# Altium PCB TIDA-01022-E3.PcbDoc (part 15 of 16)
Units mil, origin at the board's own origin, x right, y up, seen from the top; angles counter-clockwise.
Board outline 6929.13 x 11614.17 mil, 12 copper layers (L1_Top Layer, L2_GND, L3_GND, L4_Signal Layer 1, L5_GND, L6_PWR, L7_GND/PWR, L8_PWR, L9_GND/PWR, L10_Signal Layer 2, L11_GND, L12_Bottom Layer), stack 64.6 mil thick; 1733 components, 993 nets, 5987 pads, 3555 vias.

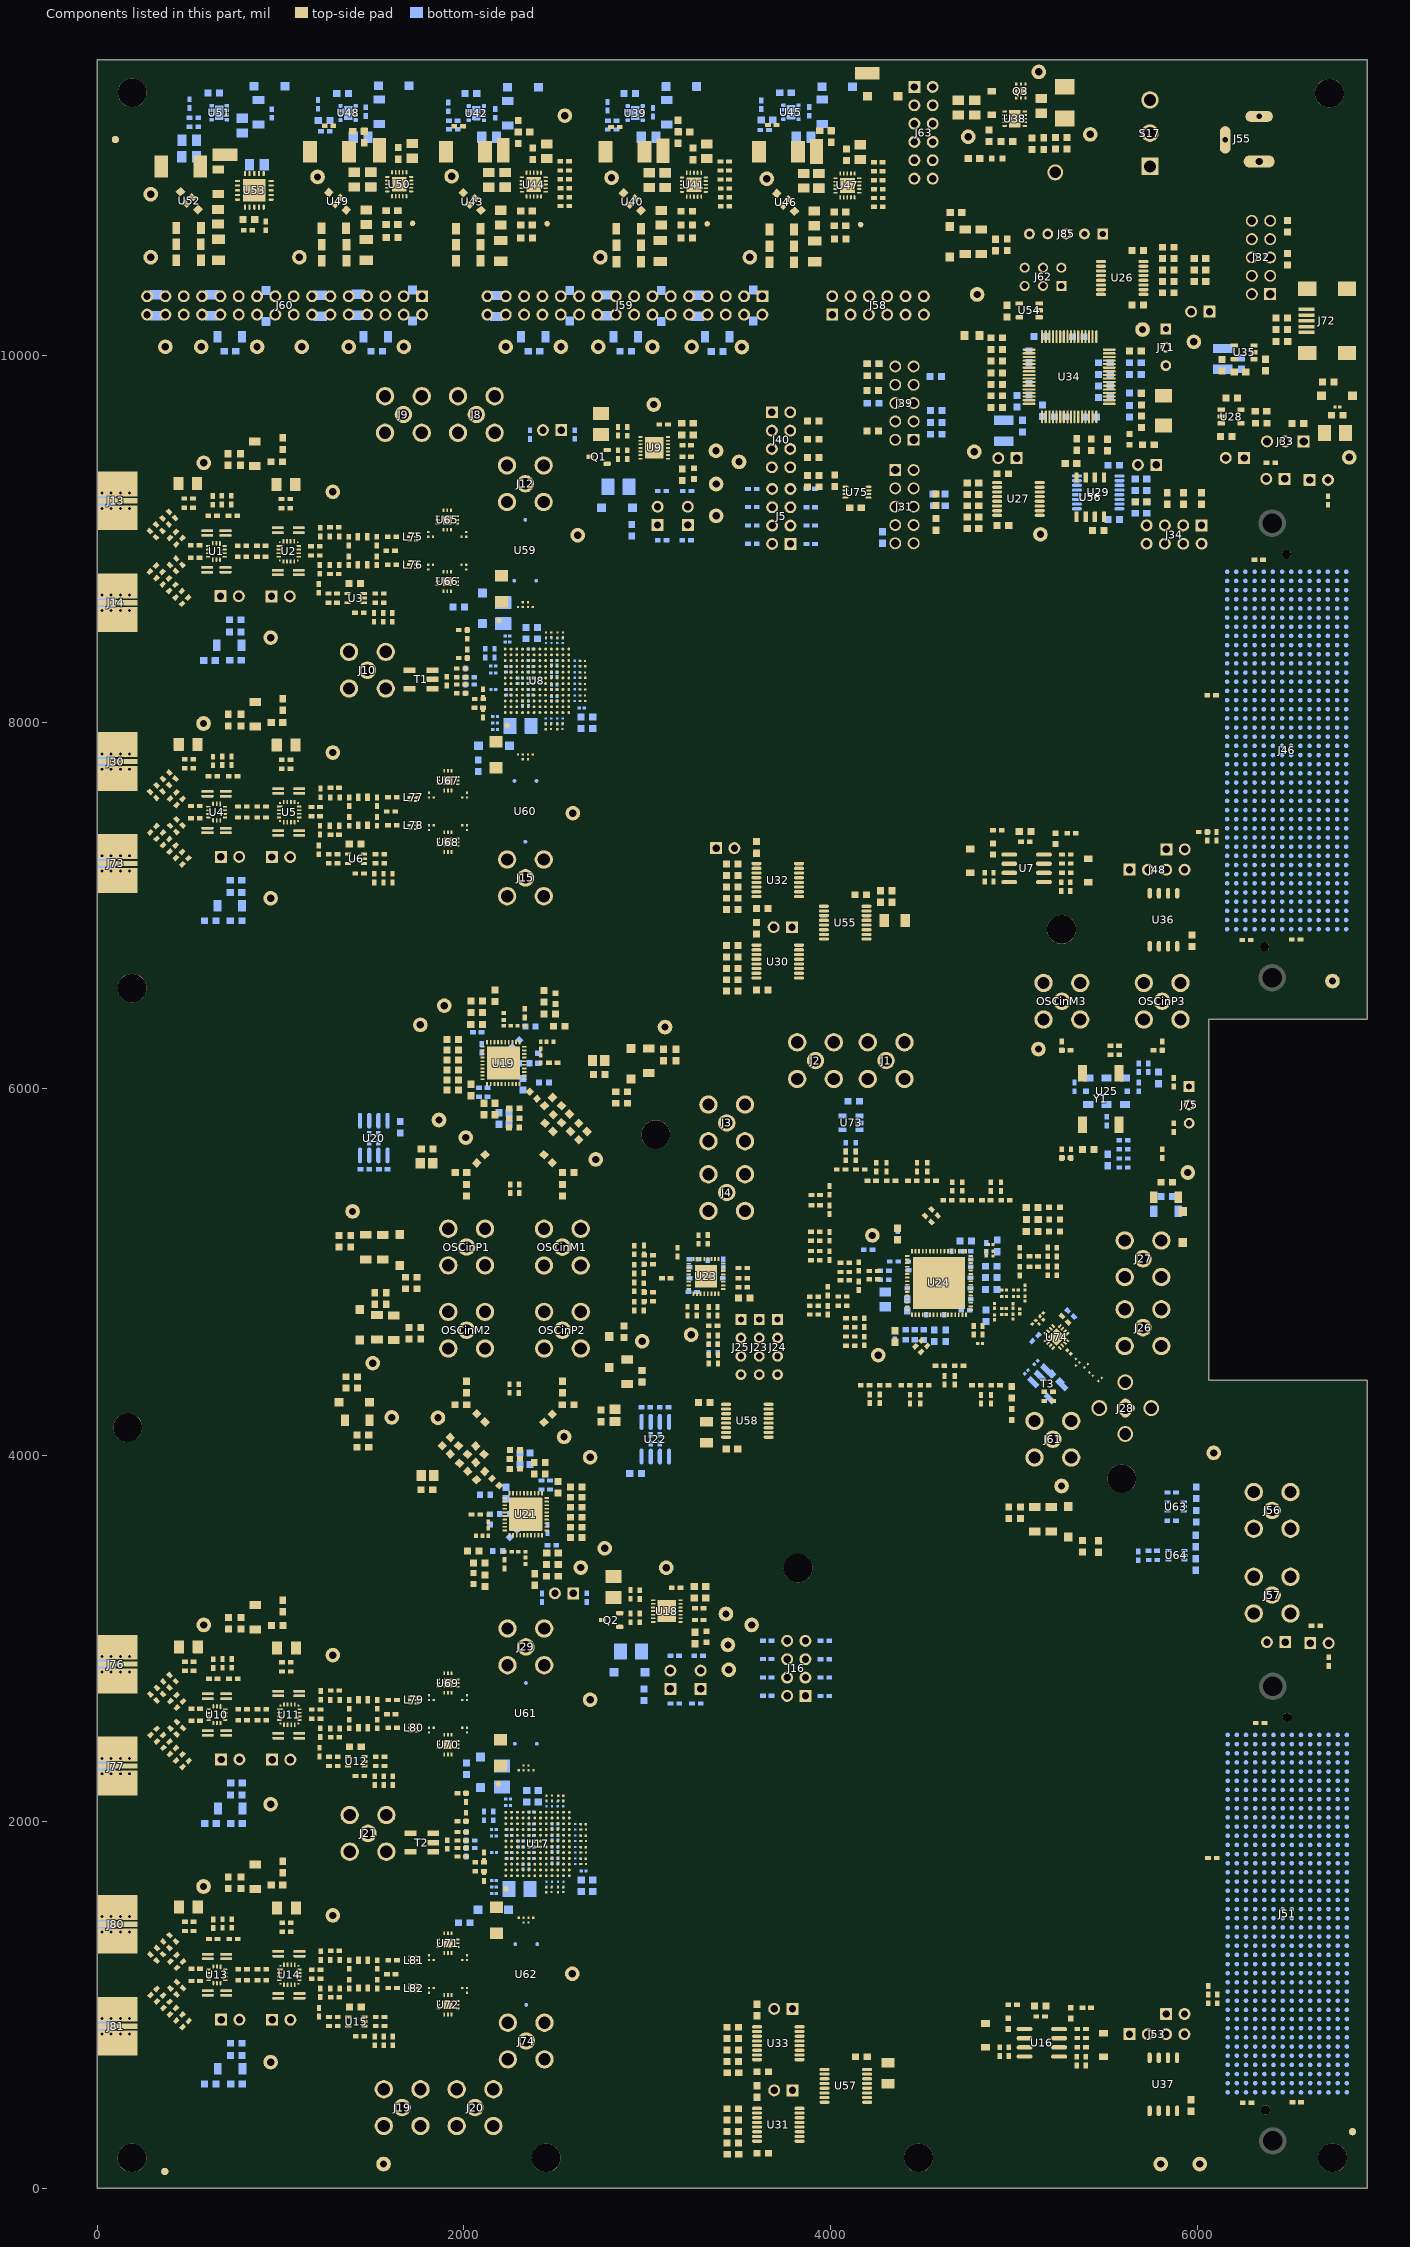
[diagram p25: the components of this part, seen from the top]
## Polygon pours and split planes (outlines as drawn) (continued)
VA1P9_ADC2 on L12_Bottom Layer "V" (solid, pour order 765): 2260,1490 2175,1490 2170,1495 2165,1500 2165,1595 2165,1690 2170,1695 2191.69,1695 2201.69,1685 2206.69,1680 2240,1680 2280,1680 2285,1675 2285,1510 2265,1490
VA1P9_ADC1 on L12_Bottom Layer "V" (solid, pour order 766): 2256.67,7836 2171.67,7836 2166.67,7841 2161.67,7846 2161.67,7941 2161.67,8029.27 2173.39,8041 2188.36,8041 2198.36,8031 2203.36,8026 2236.67,8026 2276.67,8026 2281.67,8021 2281.67,7856 2261.67,7836
VA1P1_ADC1 on L12_Bottom Layer "V" (solid, remove dead copper, pour order 767): 17 vertices, not listed, extent 2054.93,8436 2366.67,8576
NetC414_2 on L12_Bottom Layer "L1_Top Layer-No Net" (solid, pour order 782): 20 vertices, not listed, extent 5481,5542 5592,5770
DGND on L12_Bottom Layer "L1_Top Layer-No Net" (solid, pour order 783): 5606,5715 5606,5560 5615,5551 5667,5551 5673,5557 5673,5731 5666,5738 5618,5738 5606,5726
DGND on L12_Bottom Layer "L1_Top Layer-No Net" (solid, pour order 784): 5810,5448 5703,5448 5691,5436 5691,5298 5702,5287 5807,5287 5817,5297 5817,5441
V3P3_LMK61E2 on L12_Bottom Layer "L1_Top Layer-No Net" (solid, pour order 785): 5854,5285 5844,5295 5844,5452 5855,5463 6028,5463 6038,5453 6038,5300 6023,5285
DGND on L12_Bottom Layer "V" (solid, pour order 809): 2119,10255 2344,10255 2360,10239 2360,9998 2352,9990 2107,9990 2095,10002 2095,10221 2095,10245 2105,10255
DGND on L12_Bottom Layer "V" (solid, pour order 810): 2719,10255 2844,10255 2860,10239 2860,10001 2849,9990 2707,9990 2695,10002 2695,10221 2695,10245 2705,10255
DGND on L12_Bottom Layer "V" (solid, pour order 811): 3219,10255 3344,10255 3360,10239 3360,10001 3349,9990 3207,9990 3195,10002 3195,10221 3195,10245 3205,10255
V1P1V_IN on L12_Bottom Layer "V" (solid, pour order 831): 2405,10288 2392,10301 2392,10434 2410,10452 2655,10452 2664,10443 2664,10302 2650,10288
V1P9V_IN on L12_Bottom Layer "V" (solid, pour order 832): 2901,10288 2891,10298 2891,10414 2929,10452 3152,10452 3162,10442 3162,10301 3149,10288
GND on L12_Bottom Layer "V" (solid, pour order 833): 2696,10408 2696,10705 2720,10729 2721.64,10730.64 2817.51,10730.64 2850.67,10730.64 2861,10720.3 2861,10423 2861,10408 2861,10301 2851,10291 2712,10291 2696,10307
V3P3_IN on L12_Bottom Layer "V" (solid, pour order 834): 3393,10300 3393,10414 3398,10419 3878,10419 3893,10404 3893,10301 3881,10289 3404,10289 3393,10300
VA_N2P5 on L12_Bottom Layer "12" (solid, pour order 854): 743.2,8298.13 743.2,8343.13 743.2,8357.13 625.2,8357.13 616.2,8348.13 616.2,8311.13 616.2,8203.13 624.4,8194.93 732.15,8194.93 743.08,8205.85
NetC647_1 on L12_Bottom Layer "12" (solid, pour order 905): 21 vertices, not listed, extent 1199.9,11135.04 1424.41,11296.37
NetC495_1 on L12_Bottom Layer "12" (solid, pour order 908): 2991.2,11296.2 2968.15,11296.2 2966,11294.05 2966,11265.67 2960.65,11260.32 2907.31,11260.32 2901,11266.64 2901,11291.39 2816.52,11291.39 2816.52,11207.57 2816.52,11143.29 2824.94,11134.87 2980.99,11134.87 2991.2,11145.07 2991.2,11290.87
NetC538_1 on L12_Bottom Layer "12" (solid, pour order 911): 2124.2,11296.16 2101.16,11296.16 2099,11294 2099,11265.62 2093.65,11260.28 2040.31,11260.28 2034,11266.59 2034,11291.35 1949.53,11291.35 1949.53,11207.52 1949.52,11143.24 1957.94,11134.82 2113.99,11134.82 2124.2,11145.03 2124.2,11290.82
12VIN on L12_Bottom Layer "GNGN" (solid, pour order 938): 4092.72,11492.13 4098.72,11498.13 4211.98,11498.13 4215.97,11494.14 4215.97,11390.77 4210.2,11385 4095.79,11385 4092.58,11388.21
GND on L12_Bottom Layer "GNGN" (solid, remove dead copper, pour order 971): 31 vertices, not listed, extent 1168,11135.04 1819,11587
GND on L12_Bottom Layer "GNGN" (solid, remove dead copper, pour order 972): 1141.23,11376.2 1119.68,11376.2 1073.2,11376.2 1038,11341 1038,11144.09 1053.09,11129 1146,11129 1163,11146 1163,11357.05 1179.95,11373.99 1226.99,11373.99 1232.74,11379.74 1232.74,11404.16 1228.39,11408.51 1173.53,11408.51
GND on L12_Bottom Layer "GNGN" (solid, remove dead copper, pour order 973): 37 vertices, not listed, extent 1859.99,11137.39 2658.19,11587
GND on L12_Bottom Layer "GNGN" (solid, remove dead copper, pour order 974): 37 vertices, not listed, extent 2726.99,11137.44 3525.18,11587.05
GND on L12_Bottom Layer "GNGN" (solid, remove dead copper, pour order 975): 35 vertices, not listed, extent 3576,11141.57 4310.89,11591.18
VA_N2P5 on L12_Bottom Layer "12" (solid, remove dead copper, pour order 969): 748,6878 748,6923 748,6937 630,6937 621,6928 621,6891 621,6783 629.19,6774.81 736.94,6774.8 747.87,6785.72
VA_N2P5 on L12_Bottom Layer "12" (solid, pour order 967): 749.21,1953.05 749.21,1998.05 749.21,2012.05 631.21,2012.05 622.21,2003.05 622.21,1966.05 622.21,1858.05 630.41,1849.85 738.16,1849.85 749.09,1860.77
VA_N2P5 on L12_Bottom Layer "12" (solid, pour order 948): 747.59,532.43 747.59,577.43 747.59,591.43 629.59,591.43 620.59,582.43 620.59,545.43 620.59,437.43 628.79,429.23 736.54,429.23 747.47,440.15
VD1P1_ADC2 on L12_Bottom Layer "GNGN" (solid, remove dead copper, pour order 1066): 2881.44,2982 2759,2982 2759,2769.14 2735.72,2745.86 2631.06,2745.86 2612.87,2727.67 2612.87,2609.13 2622,2600 2856.5,2600 2872,2615.5 2872,2862.68 2893.32,2884 2893.32,2970.12
VD1P1_ADC1 on L12_Bottom Layer "GNGN" (solid, remove dead copper, pour order 1080): 2813.68,9335.41 2691.24,9335.41 2691.24,9122.55 2667.96,9099.27 2563.3,9099.27 2545.1,9081.08 2545.1,8962.55 2554.24,8953.41 2788.74,8953.41 2804.24,8968.91 2804.24,9216.09 2825.56,9237.41 2825.56,9323.53
V1P1V on L12_Bottom Layer "h" (solid, pour order 1082): 2858.26,9060.01 2852.94,9065.33 2852.94,9192.18 2867.18,9206.41 2969.31,9206.41 2986.27,9189.45 2986.27,9068.01 2978.26,9060
DGND on L12_Bottom Layer "12" (solid, remove dead copper, pour order 1086): 54 vertices, not listed, extent 1262,70 6899,10776
NetC695_2 on L6_PWR "L4_Signal Layer 1-No Net" (solid, remove dead copper, pour order 1060): 20,11038 20,10323.25 70.25,10273 1005,10273 1010,10278 1010,11320.56 955.56,11375 955.56,11577.43 945.99,11587 451.98,11587 379.83,11514.85 379.83,11397.83 355,11373
VA_N2P5_LMH5401_4 on L6_PWR "GNGN" (solid, remove dead copper, pour order 1008): 19 vertices, not listed, extent 358.46,565.46 1642.67,1686.3
VA_N2P5_LMH5401_3 on L6_PWR "GNGN" (solid, remove dead copper, pour order 1006): 19 vertices, not listed, extent 358.38,1984.8 1642.59,3105.64
VA_N2P5_LMH5401_2 on L6_PWR "GNGN" (solid, remove dead copper, pour order 1004): 19 vertices, not listed, extent 356.87,6909.03 1641.07,8029.87
VA_N2P5_LMH5401_1 on L6_PWR "GNGN" (solid, remove dead copper, pour order 981): 19 vertices, not listed, extent 355.07,8331.16 1639.28,9452
12VIN on L6_PWR "GNGN" (solid, pour order 970): 21 vertices, not listed, extent 977,11385 4268.73,11587
GND on L6_PWR "L4_Signal Layer 1-No Net" (solid, remove dead copper, pour order 966): 1351.38,11364 1060.42,11364 1038,11341.58 1038,10273 1801.91,10273 1813.91,10285 1819,10290.09 1819,10360.89 1819,11343.69 1798.69,11364
GND on L6_PWR "L4_Signal Layer 1-No Net" (solid, remove dead copper, pour order 965): 1860,11356.22 1860,10312 1881,10291 2658,10291 2658,11350.39 2644.39,11364 2352.82,11364 2338.34,11378.48 2338.34,11486.15 2328.48,11496 2042.15,11496 1914.23,11496 1860,11441.77 1860,11358.14
GND on L6_PWR "L4_Signal Layer 1-No Net" (solid, remove dead copper, pour order 964): 2696,11330 2696,10297 2702,10291 3164.19,10291 3165,10291.81 3165,10444 3525,10804 3525,11356.56 3517.56,11364 2708.43,11364 2696,11351.57
GND on L6_PWR "L4_Signal Layer 1-No Net" (solid, remove dead copper, pour order 963): 22 vertices, not listed, extent 3194,10291 4609,11587
V3P3_LMX2RF on L6_PWR "12" (solid, pour order 869): 1277.39,4363.39 1277.39,3765.61 1764,3279 2425,3279 2437,3291 2437,3526 2413,3550 2329,3550 2219,3660 1792,3660 1667,3785 1667,4337 1633,4371 1285,4371
V3P3_LMX2 on L6_PWR "12" (solid, pour order 868): 21 vertices, not listed, extent 1277.39,3310 3042,4642.68
V3P3_LMX1RF on L6_PWR "12" (solid, pour order 865): 2339,6260 2299,6220 1717,6220 1698,6239 1698,6391 1812,6505 1852,6545 2330,6545 3092,6545 3178,6545 3198.57,6524.43 3198.57,6400.77 3198.57,6296.57 3162,6260
V3P3 on L6_PWR "12" (solid, pour order 860): 17 vertices, not listed, extent 1277.39,4445.76 2837,5340
V3P3_LMX1 on L6_PWR "12" (solid, pour order 859): 1277.39,5185.61 1277.39,5962.43 1512.96,6198 2291.29,6198 2350.47,6257.18 2418.92,6257.18 2816.82,6257.18 2839.61,6234.39 2839.61,5481.61 2727,5369 1899,5369 1705.3,5175.3 1287.7,5175.3
V3P3_VDD on L6_PWR "12" (solid, pour order 858): 34 vertices, not listed, extent 2627,6376.24 6898,10801
V3P3_VDD on L6_PWR "12" (solid, pour order 857): 29 vertices, not listed, extent 2684,70 6082.44,4333
VA_N2P5 on L6_PWR "12" (solid, pour order 855): 44 vertices, not listed, extent 53,421.89 1003,10255
V3P3_LMK48XX on L6_PWR "V" (solid, pour order 815): 20 vertices, not listed, extent 3254,3743 6019,6344
V3P3_LMK61E2 on L6_PWR "V" (solid, pour order 814): 5702,5287 5526,5287 5400,5413 5074,5739 5074,6239 5074,6625 5126,6677 5919,6677 6018,6578 6018,5305.28 5999.72,5287 5703,5287
V3P3_LMK00304 on L6_PWR "V" (solid, pour order 813): 3741,4362 2912,4362 2882,4392 2860,4414 2860,4960 2860,5206 2898,5244 3372,5244 3678,5244 3753,5169 3760.74,5161.26 3760.74,4758 3760.74,4381.74
VREGIN on L6_PWR "V" (solid, pour order 812): 18 vertices, not listed, extent 5043.3,9556.44 5863.31,10075
V3P3 on L6_PWR "12" (solid, pour order 895): 4709,10776 4612,10776 4600,10764 4600,10216 4534,10150 3405,10150 3392,10137 3392,10000 3402,9990 4594,9990 4664,10060 4720,10116 4720,10765
GND on L6_PWR "GNGN" (solid, remove dead copper, pour order 978): 4586.81,11587 6805,11587 6865,11527 6865,10886 6808,10829 4604,10829 4599,10824 4576.5,10846.5 4576.5,11581
VD1P1_ADC2 on L6_PWR "GNGN" (solid, remove dead copper, pour order 1070): 2747,1546.22 2421.78,1546.22 2405.33,1562.67 2405.33,2469.31 2702.36,2766.34 2735.64,2799.62 2807.45,2799.62 2852.71,2799.62 2873.33,2779 2873.33,1578.26 2841,1545.93
V1P1V on L6_PWR "GNGN" (solid, remove dead copper, pour order 1072): 23 vertices, not listed, extent 1969.98,2259.91 3080.52,3008.69
VA1P9_ADC2 on L6_PWR "GNGN" (solid, remove dead copper, pour order 1074): 30 vertices, not listed, extent 1848.05,1034 4066.64,3026.61
VA1P9_ADC1 on L6_PWR "GNGN" (solid, remove dead copper, pour order 1076): 27 vertices, not listed, extent 1844.71,7380 3995.09,9308
VD1P1_ADC1 on L6_PWR "GNGN" (solid, remove dead copper, pour order 1078): 2743.67,7892.21 2418.45,7892.21 2402,7908.67 2402,8872.44 2675.18,9145.62 2804.12,9145.62 2825,9124.74 2825,7960.21 2756.76,7892.17
V1P1V on L6_PWR "GNGN" (solid, remove dead copper, pour order 1084): 20 vertices, not listed, extent 1966.65,8605.9 3000,9310.58
NetC695_2 on L8_PWR "L4_Signal Layer 1-No Net" (solid, remove dead copper, pour order 1062): 20,11038 20,10323.25 70.25,10273 1005,10273 1010,10278 1010,11320.56 955.56,11375 955.56,11577.43 945.99,11587 451.98,11587 379.45,11514.47 379.45,11397.45 355,11373
VA2P5_LMH5401_4 on L8_PWR "GNGN" (solid, remove dead copper, pour order 1002): 1343.68,836.04 403.73,836.04 371.19,868.58 371.19,1673.05 397.82,1699.68 409.89,1711.75 873.16,1711.75 916.46,1711.75 1036.21,1592 1300.36,1592 1335.64,1556.72 1358,1534.36 1358,850.36
VA2P5_LMH5401_3 on L8_PWR "GNGN" (solid, remove dead copper, pour order 1000): 1343.68,2256.32 403.73,2256.32 371.19,2288.86 371.19,3093.33 397.82,3119.95 409.89,3132.03 873.16,3132.03 916.46,3132.03 1036.21,3012.28 1300.36,3012.28 1335.64,2977 1358,2954.64 1358,2270.64
VA2P5_LMH5401_2 on L8_PWR "GNGN" (solid, remove dead copper, pour order 998): 1343.68,7180.56 403.73,7180.56 371.19,7213.09 371.19,8017.56 397.82,8044.19 409.89,8056.26 873.16,8056.26 916.46,8056.26 1036.21,7936.51 1300.36,7936.51 1335.64,7901.23 1358,7878.87 1358,7194.87
VA2P5_LMH5401_1 on L8_PWR "GNGN" (solid, remove dead copper, pour order 980): 1343.68,8602.68 403.73,8602.68 371.19,8635.22 371.19,9439.69 397.82,9466.32 409.89,9478.39 873.16,9478.39 922.33,9478.39 1030.72,9370 1289,9370 1335.64,9323.36 1358,9301 1358,8617
12VIN on L8_PWR "GNGN" (solid, pour order 961): 21 vertices, not listed, extent 977,11385 4268.73,11587
GND on L8_PWR "L4_Signal Layer 1-No Net" (solid, remove dead copper, pour order 960): 1351.38,11364 1060.42,11364 1038,11341.58 1038,10273 1801.91,10273 1813.91,10285 1819,10290.09 1819,10360.89 1819,11343.69 1798.69,11364
GND on L8_PWR "L4_Signal Layer 1-No Net" (solid, remove dead copper, pour order 959): 1860,11356.22 1860,10312 1881,10291 2658,10291 2658,11350.39 2644.39,11364 2352.82,11364 2338.34,11378.48 2338.34,11486.15 2328.48,11496 2042.15,11496 1914.23,11496 1860,11441.77 1860,11358.14
GND on L8_PWR "L4_Signal Layer 1-No Net" (solid, remove dead copper, pour order 958): 2696,11330 2696,10297 2702,10291 3164.19,10291 3165,10291.81 3165,10444 3525,10804 3525,11356.56 3517.56,11364 2708.43,11364 2696,11351.57
GND on L8_PWR "L4_Signal Layer 1-No Net" (solid, remove dead copper, pour order 957): 22 vertices, not listed, extent 3194,10291 4609,11587
V3P3_VDD on L8_PWR "12" (solid, pour order 863): 19 vertices, not listed, extent 2886,106 6083,7428
VDDL19 on L8_PWR "12" (solid, pour order 862): 4648,10658 4648,7526 4704,7470 4723,7451 5722,7451 6051,7451 6082,7482 6082,8935 6106,8959 6821,8959 6898,9036 6898,10751 6848,10801 4791,10801 4653,10663
V3P3 on L8_PWR "12" (solid, pour order 861): 22 vertices, not listed, extent 2374,3460 5598,10255
VA2P5 on L8_PWR "12" (solid, pour order 856): 45 vertices, not listed, extent 683,1617.22 1804,10255
VA1P1_ADC2 on L8_PWR "V" (solid, pour order 822): 2145.34,2235 2130.33,2220 2130.33,1743 2155.33,1718 2599,1718 2615.33,1734.33 2615.33,2209 2615.33,2220 2600.33,2235
VA1P1_ADC1 on L8_PWR "V" (solid, pour order 821): 2142.01,8581 2127,8566 2127,8089 2149,8067 2574,8067 2612,8105 2612,8555 2612,8566 2597,8581
VA1P9_ADC1 on L8_PWR "12" (solid, pour order 875): 2640,9187 2640,8061 2617,8038 2177,8038 2175,8036 2175,7864 2183,7856 2831,7856 2884,7909 2884,9185 2846,9223 2658,9223 2640,9205
VA1P9_ADC2 on L8_PWR "12" (solid, pour order 876): 2628.18,2698.18 2628.18,1722.18 2594,1688 2172,1688 2167,1683 2167,1511 2180.09,1497.91 2819.18,1497.91 2864,1542.73 2864,2702 2848,2718 2648,2718
GND on L8_PWR "GNGN" (solid, remove dead copper, pour order 979): 4586.81,11587 6856.56,11587 6874.56,11569 6874.56,10897.72 6805.84,10829 4604,10829 4599,10824 4576.5,10846.5 4576.5,11581
DGND on L2_GND "12" (solid, remove dead copper, pour order 879): 112 vertices, not listed, extent 1262,70 6899,10776
AGND on L2_GND "12" (solid, remove dead copper, pour order 878): 97 vertices, not listed, extent 17.27,71 2555.33,10255
GND on L2_GND "12" (solid, pour order 840): 1912.86,11496 1860,11443.14 1860,10312 1881,10291 1966,10291 4519,10291 4572,10344 4572,10797 4609,10834 4609,11087 4585,11111 4391.28,11111 4391.27,11437.55 4332.82,11496 4204.99,11496
GND on L2_GND "12" (solid, pour order 839): 22 vertices, not listed, extent 20,10273 6865,11587
GND on L11_GND "12" (solid, pour order 1056): 22 vertices, not listed, extent 20,10273 6865,11587
GND on L11_GND "12" (solid, pour order 949): 1912.86,11496 1860,11443.14 1860,10312 1881,10291 1966,10291 4519,10291 4572,10344 4572,10797 4609,10834 4609,11087 4585,11111 4391.28,11111 4391.27,11437.55 4332.82,11496 4204.99,11496
DGND on L11_GND "12" (solid, remove dead copper, pour order 853): 54 vertices, not listed, extent 1262,70 6899,10776
AGND on L11_GND "12" (solid, remove dead copper, pour order 852): 26 vertices, not listed, extent 2152,2042.38 2554.99,3108.38
AGND on L11_GND "12" (solid, remove dead copper, pour order 851): 24 vertices, not listed, extent 2121.91,650.23 2522,1716.23
AGND on L11_GND "12" (solid, remove dead copper, pour order 850): 25 vertices, not listed, extent 2140,6996.2 2517,8062.2
AGND on L11_GND "12" (solid, remove dead copper, pour order 849): 25 vertices, not listed, extent 2160,8388 2552,9454
AGND on L11_GND "12" (solid, remove dead copper, pour order 884): 47 vertices, not listed, extent 17.27,71 1804,10255
GND on L5_GND "12" (solid, pour order 1050): 22 vertices, not listed, extent 20,10273 6865,11587
GND on L5_GND "12" (solid, pour order 942): 1912.86,11496 1860,11443.14 1860,10312 1881,10291 1966,10291 4519,10291 4572,10344 4572,10797 4609,10834 4609,11087 4585,11111 4391.28,11111 4391.27,11437.55 4332.82,11496 4204.99,11496
DGND on L5_GND "12" (solid, remove dead copper, pour order 882): 101 vertices, not listed, extent 873,70 6899,10776
AGND on L5_GND "12" (solid, remove dead copper, pour order 883): 85 vertices, not listed, extent 17.27,71 2521.36,10255
GND on L3_GND "12" (solid, pour order 1048): 22 vertices, not listed, extent 20,10273 6865,11587
DGND on L3_GND "12" (solid, remove dead copper, pour order 881): 112 vertices, not listed, extent 1262,70 6899,10776
AGND on L3_GND "12" (solid, remove dead copper, pour order 880): 97 vertices, not listed, extent 17.27,71 2555.33,10255
GND on L3_GND "12" (solid, pour order 940): 1912.86,11496 1860,11443.14 1860,10312 1881,10291 1966,10291 4519,10291 4572,10344 4572,10797 4609,10834 4609,11087 4585,11111 4391.28,11111 4391.27,11437.55 4332.82,11496 4204.99,11496
GND on L7_GND/PWR "12" (solid, pour order 1052): 22 vertices, not listed, extent 20,10273 6865,11587
GND on L7_GND/PWR "12" (solid, pour order 944): 1912.86,11496 1860,11443.14 1860,10312 1881,10291 1966,10291 4519,10291 4572,10344 4572,10797 4609,10834 4609,11087 4585,11111 4391.28,11111 4391.27,11437.55 4332.82,11496 4204.99,11496
AGND on L7_GND/PWR "12" (solid, remove dead copper, pour order 886): 89 vertices, not listed, extent 17.27,71 2555.33,10255
V1P9V on L7_GND/PWR "12" (solid, remove dead copper, pour order 887): 100 vertices, not listed, extent 1262,103 6898,10776
GND on L9_GND/PWR "12" (solid, pour order 1054): 22 vertices, not listed, extent 20,10273 6865,11587
GND on L9_GND/PWR "12" (solid, pour order 946): 1912.86,11496 1860,11443.14 1860,10312 1881,10291 1966,10291 4519,10291 4572,10344 4572,10797 4609,10834 4609,11087 4585,11111 4391.28,11111 4391.27,11437.55 4332.82,11496 4204.99,11496
AGND on L9_GND/PWR "12" (solid, remove dead copper, pour order 888): 87 vertices, not listed, extent 17.27,71 2555.33,10255
V1P1V on L9_GND/PWR "12" (solid, remove dead copper, pour order 889): 100 vertices, not listed, extent 1262,103 6899,10776
V1P9V on L4_Signal Layer 1 "L1_Top Layer-No Net" (solid, pour order 864): 17 vertices, not listed, extent 2787,8961 6898,10801
VA2P5 on L4_Signal Layer 1 "L4_Signal Layer 1-No Net" (solid, remove dead copper, pour order 935): 50 vertices, not listed, extent 17,1587 1160,9490
GND on L4_Signal Layer 1 "L4_Signal Layer 1-No Net" (solid, remove dead copper, pour order 934): 22 vertices, not listed, extent 3194,10291 4609,11587
GND on L4_Signal Layer 1 "L4_Signal Layer 1-No Net" (solid, remove dead copper, pour order 933): 2696,11330 2696,10297 2702,10291 3164.19,10291 3165,10291.81 3165,10444 3525,10804 3525,11356.56 3517.56,11364 2708.43,11364 2696,11351.57
GND on L4_Signal Layer 1 "L4_Signal Layer 1-No Net" (solid, remove dead copper, pour order 932): 1860,11356.22 1860,10312 1881,10291 2658,10291 2658,11350.39 2644.39,11364 2352.82,11364 2338.34,11378.48 2338.34,11486.15 2328.48,11496 2042.15,11496 1914.23,11496 1860,11441.77 1860,11358.14
GND on L4_Signal Layer 1 "L4_Signal Layer 1-No Net" (solid, remove dead copper, pour order 931): 1351.38,11364 1060.42,11364 1038,11341.58 1038,10273 1801.91,10273 1813.91,10285 1819,10290.09 1819,10360.89 1819,11343.69 1798.69,11364
NetC695_2 on L4_Signal Layer 1 "L4_Signal Layer 1-No Net" (solid, remove dead copper, pour order 930): 20,11038 20,10323.25 70.25,10273 1005,10273 1010,10278 1010,11320.56 955.56,11375 955.56,11577.43 945.99,11587 451.98,11587 379.45,11514.47 379.45,11397.45 355,11373
12VIN on L4_Signal Layer 1 "GNGN" (solid, pour order 939): 21 vertices, not listed, extent 977,11385 4268.73,11587
GND on L4_Signal Layer 1 "GNGN" (solid, remove dead copper, pour order 976): 4586.81,11587 6856.56,11587 6865,11578.56 6865,10885.62 6808.38,10829 4604,10829 4599,10824 4576.5,10846.5 4576.5,11581
NetC695_2 on L10_Signal Layer 2 "L4_Signal Layer 1-No Net" (solid, remove dead copper, pour order 1064): 20,11038 20,10323.25 70.25,10273 1005,10273 1010,10278 1010,11320.56 955.56,11375 955.56,11577.43 945.99,11587 451.98,11587 379.45,11514.47 379.45,11397.45 355,11373
12VIN on L10_Signal Layer 2 "GNGN" (solid, pour order 955): 21 vertices, not listed, extent 977,11385 4268.73,11587
GND on L10_Signal Layer 2 "L4_Signal Layer 1-No Net" (solid, remove dead copper, pour order 954): 1351.38,11364 1060.42,11364 1038,11341.58 1038,10273 1801.91,10273 1813.91,10285 1819,10290.09 1819,10360.89 1819,11343.69 1798.69,11364
GND on L10_Signal Layer 2 "L4_Signal Layer 1-No Net" (solid, remove dead copper, pour order 953): 1860,11356.22 1860,10312 1881,10291 2658,10291 2658,11350.39 2644.39,11364 2352.82,11364 2338.34,11378.48 2338.34,11486.15 2328.48,11496 2042.15,11496 1914.23,11496 1860,11441.77 1860,11358.14
GND on L10_Signal Layer 2 "L4_Signal Layer 1-No Net" (solid, remove dead copper, pour order 952): 2696,11330 2696,10297 2702,10291 3164.19,10291 3165,10291.81 3165,10444 3525,10804 3525,11356.56 3517.56,11364 2708.43,11364 2696,11351.57
GND on L10_Signal Layer 2 "L4_Signal Layer 1-No Net" (solid, remove dead copper, pour order 951): 22 vertices, not listed, extent 3194,10291 4609,11587
VA_N2P5 on L10_Signal Layer 2 "L1_Top Layer-No Net" (solid, pour order 912): 742,10255 78,10255 17.27,10194.27 17.27,546.06 192.33,371 943.42,371 1650,1077.58 1650,10014.2 1409.19,10255
GND on L10_Signal Layer 2 "GNGN" (solid, remove dead copper, pour order 977): 4586.81,11587 6856.56,11587 6874.56,11569 6874.56,10897.72 6805.84,10829 4604,10829 4599,10824 4576.5,10846.5 4576.5,11581
GND on Bottom Solder "GNGN" (solid): 1769,10667 1451,10667 1385,10733 1062,10733 1037,10708 1037,10506.47 1058.47,10485 1540,10485 1760,10485 1810,10535 1810,10656 1799,10667
GND on Bottom Solder "GNGN" (solid): 1861,10698.26 1861,10500 1876,10485 1889,10485 2528,10485 2562,10519 2562,10703.26 2532.26,10733 1871,10733 1861,10723
GND on Bottom Solder "GNGN" (solid): 3293.71,10712.29 3273,10733 2704.24,10733 2696,10724.76 2696,10489.71 2700.71,10485 3184,10485 3293.71,10594.71
GND on Bottom Solder "GNGN" (solid): 4237,10733 3519.7,10733 3494.7,10708 3494.7,10506.47 3516.17,10485 3997.7,10485 4246,10485 4267.7,10506.7 4267.7,10702.3
GND on Bottom Solder "GNGN" (solid): 968.3,10733 251,10733 226,10708 226,10506.47 247.47,10485 729,10485 977.3,10485 996,10503.7 996,10705.3
GND on Bottom Solder "GNGN" (solid): 19 vertices, not listed, extent 1168,11285 1633,11587
GND on Bottom Solder "GNGN" (solid): 19 vertices, not listed, extent 1867.79,11284.78 2332.79,11586.78
GND on Bottom Solder "GNGN" (solid): 19 vertices, not listed, extent 2734.79,11284.83 3199.79,11586.83
GND on Bottom Solder "GNGN" (solid): 19 vertices, not listed, extent 3583.8,11288.96 4048.8,11590.96
NetC695_2 on Bottom Solder "GNGN" (solid): 19 vertices, not listed, extent 464.68,11286.82 774,11588.82

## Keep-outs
Keep-Out Layer:
  circle w10: c6412.44,259.01 r99.18
  circle w10: c6412.44,2739.01 r99.18
  circle w10: c6409.11,6605.01 r99.18
  circle w10: c6409.11,9085.01 r99.18
  text ".Layer_Name" at -2293.76,-2323.68 h60

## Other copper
L1_Top Layer:
  drawing of 110 lines, arcs and shapes, not listed
  text "L1_TOP LAYER" at -2294.53,-2305.19 h60
L4_Signal Layer 1:
  pour cut-out: 4334.26,10849.78 4334.26,11068.47 4160.44,11242.29 4051.79,11242.29 4051.79,11253 4164.67,11253 4344.35,11073.32 4344.35,10850
  text "'.Layer_Name'" at -2294.32,-2310.1 h60
L10_Signal Layer 2:
  pour cut-out: 4334.26,10849.78 4334.26,11068.47 4160.44,11242.29 4051.79,11242.29 4051.79,11253 4164.67,11253 4344.35,11073.32 4344.35,10850
  pour cut-out: 1650,2139.98 1308.61,2139.98 1244.63,2076 1244.63,1832.69 1650,1427.32
  pour cut-out: 1650,6715.07 1256.93,6322 1256.93,3753.07 1650,3360 1650,6715.07
  pour cut-out: 1650,9881.34 1626.66,9858 1492.94,9858 1448,9813.06 1448,9494.06 1486.06,9456 1639.07,9456 1650,9445.07
  pour cut-out: 1650,8510.93 1620.07,8481 1297.61,8481 1237.31,8420.7 1237.31,8184.98 1666,7756.29 1666,7755
  text "'.Layer_Name'" at -2296.32,-2321.1 h60
L2_GND:
  pour cut-out: 1188.92,1305.83 1188.92,1029.87 1202.49,1016.3 1625.08,1016.3 1660.39,1051.61 1660.39,1307.04 1638.13,1329.3 1212.39,1329.3
  pour cut-out: 1188.84,2725.17 1188.84,2449.21 1202.41,2435.64 1625,2435.64 1660.32,2470.95 1660.32,2726.38 1638.06,2748.64 1212.32,2748.64
  pour cut-out: 1187.32,7649.4 1187.32,7373.44 1200.89,7359.87 1623.49,7359.87 1658.8,7395.18 1658.8,7650.61 1636.54,7672.87 1210.8,7672.87
  pour cut-out: 1185.53,9071.53 1185.53,8795.57 1199.1,8782 1621.69,8782 1657,8817.31 1657,9072.74 1634.74,9095 1209,9095
  pour cut-out: 3201,10291 3194,10298 3194,10422 3560,10788 3560,11330 3525,11330 3525,10804 3165,10444 3165,10291.81 3165.81,10291
  pour cut-out: 2702,10291 2696,10297 2696,11330 2658,11330 2658,10291
  pour cut-out: 1038,10272.51 1038,11352.34 1010,11352.34 1010,10273
  pour cut-out: 4334.26,10849.78 4334.26,11068.47 4160.44,11242.29 4051.79,11242.29 4051.79,11253 4164.67,11253 4344.35,11073.32 4344.35,10850
  text "'.Layer_Name'" at -2293.32,-2319.1 h60
L5_GND:
  pour cut-out: 4334.26,10849.78 4334.26,11068.47 4160.44,11242.29 4051.79,11242.29 4051.79,11253 4164.67,11253 4344.35,11073.32 4344.35,10850
  pour cut-out: 1038,10272.51 1038,11352.34 1010,11352.34 1010,10273
  pour cut-out: 2702,10291 2696,10297 2696,11330 2658,11330 2658,10291
  pour cut-out: 3201,10291 3194,10298 3194,10422 3560,10788 3560,11330 3525,11330 3525,10804 3165,10444 3165,10291.81 3165.81,10291
  text "'.Layer_Name'" at -2296.32,-2322.1 h60
L6_PWR:
  pour cut-out: 4334.26,10849.78 4334.26,11068.47 4160.44,11242.29 4051.79,11242.29 4051.79,11253 4164.67,11253 4344.35,11073.32 4344.35,10850
  text "'.Layer_Name'" at -2296.32,-2322.1 h60
L7_GND/PWR:
  pour cut-out: 4334.26,10849.78 4334.26,11068.47 4160.44,11242.29 4051.79,11242.29 4051.79,11253 4164.67,11253 4344.35,11073.32 4344.35,10850
  pour cut-out: 1038,10272.51 1038,11352.34 1010,11352.34 1010,10273
  pour cut-out: 2702,10291 2696,10297 2696,11330 2658,11330 2658,10291
  pour cut-out: 3201,10291 3194,10298 3194,10422 3560,10788 3560,11330 3525,11330 3525,10804 3165,10444 3165,10291.81 3165.81,10291
  text "'.Layer_Name'" at -2295.32,-2318.1 h60
L3_GND:
  pour cut-out: 4334.26,10849.78 4334.26,11068.47 4160.44,11242.29 4051.79,11242.29 4051.79,11253 4164.67,11253 4344.35,11073.32 4344.35,10850
  pour cut-out: 1038,10272.51 1038,11352.34 1010,11352.34 1010,10273
  pour cut-out: 2702,10291 2696,10297 2696,11330 2658,11330 2658,10291
  pour cut-out: 3201,10291 3194,10298 3194,10422 3560,10788 3560,11330 3525,11330 3525,10804 3165,10444 3165,10291.81 3165.81,10291
  text "'.Layer_Name'" at -2294.32,-2314.1 h60
L8_PWR:
  pour cut-out: 4334.26,10849.78 4334.26,11068.47 4160.44,11242.29 4051.79,11242.29 4051.79,11253 4164.67,11253 4344.35,11073.32 4344.35,10850
  text "'.Layer_Name'" at -2296.32,-2319.1 h60
L9_GND/PWR:
  pour cut-out: 4334.26,10849.78 4334.26,11068.47 4160.44,11242.29 4051.79,11242.29 4051.79,11253 4164.67,11253 4344.35,11073.32 4344.35,10850
  pour cut-out: 1038,10272.51 1038,11352.34 1010,11352.34 1010,10273
  pour cut-out: 2702,10291 2696,10297 2696,11330 2658,11330 2658,10291
  pour cut-out: 3201,10291 3194,10298 3194,10422 3560,10788 3560,11330 3525,11330 3525,10804 3165,10444 3165,10291.81 3165.81,10291
  text "'.Layer_Name'" at -2295.32,-2320.1 h60
L11_GND:
  pour cut-out: 4334.26,10849.78 4334.26,11068.47 4160.44,11242.29 4051.79,11242.29 4051.79,11253 4164.67,11253 4344.35,11073.32 4344.35,10850
  pour cut-out: 1038,10272.51 1038,11352.34 1010,11352.34 1010,10273
  pour cut-out: 2702,10291 2696,10297 2696,11330 2658,11330 2658,10291
  pour cut-out: 3201,10291 3194,10298 3194,10422 3560,10788 3560,11330 3525,11330 3525,10804 3165,10444 3165,10291.81 3165.81,10291
  text "'.Layer_Name'" at -2295.32,-2320.1 h60
L12_Bottom Layer:
  pour cut-out: 2410.33,2361 2651.33,2602 6093.33,2602 6866.33,2602 6899.33,2569 6899.33,422 6855.33,378 6120.33,378 6081.33,417 6081.33,1045 2789.33,1045 2410.33,1424
  pour cut-out: 2407,8707 2648,8948 6090,8948 6863,8948 6896,8915 6896,6768 6852,6724 6117,6724 6078,6763 6078,7391 2786,7391 2407,7770
  pour cut-out: 5259.87,4804.87 5371.08,4694.08 5306.5,4629.5 5233,4703 5175,4645 5231,4589 5301,4659 5369.5,4590.5 5263.5,4484.5 5101.5,4646.5
  pour cut-out: 5319.16,4642.16 5319.16,4640.84 5303.5,4656.5 5303.5,4661.5 5326.41,4684.41 5341,4669.82 5341,4664
  region net NetC695_2: 688.18,11357.46 688.18,11410.4 692.78,11415 646.07,11415 642,11410.92 642,11343.1 643.09,11342 685.18,11342 686,11342.82
  region net GND: 1412.78,11300.28 1392.5,11300.28 1391.74,11299.51 1391.74,11282.96 1391.78,11282.92 1344.39,11282.92 1344.32,11283 1344.32,11453.25 1344.66,11453.59 1391.78,11453.59 1391.74,11453.55 1391.74,11322.4 1393.94,11320.2 1475.68,11320.2 1477,11318.89 1477,11291.95 1475,11289.95 1443.55,11289.95 1433.21,11300.29
  region net GND: 2112.57,11300.06 2092.29,11300.06 2091.53,11299.3 2091.53,11282.75 2091.57,11282.71 2044.18,11282.71 2044.11,11282.78 2044.11,11453.03 2044.45,11453.37 2091.57,11453.37 2091.53,11453.33 2091.53,11322.19 2093.73,11319.99 2175.48,11319.99 2176.79,11318.67 2176.79,11291.74 2174.79,11289.74 2143.34,11289.74 2133.01,11300.07
  region net GND: 2979.57,11300.11 2959.29,11300.11 2958.53,11299.35 2958.53,11282.79 2958.57,11282.75 2911.18,11282.75 2911.11,11282.83 2911.11,11453.08 2911.44,11453.42 2958.57,11453.42 2958.53,11453.38 2958.53,11322.23 2960.73,11320.03 3042.47,11320.03 3043.79,11318.72 3043.79,11291.78 3041.79,11289.78 3010.34,11289.78 3000,11300.12
  region net GND: 3828.58,11304.24 3808.3,11304.24 3807.53,11303.48 3807.53,11286.92 3807.57,11286.88 3760.19,11286.88 3760.11,11286.96 3760.11,11457.21 3760.45,11457.55 3807.57,11457.55 3807.53,11457.51 3807.53,11326.36 3809.73,11324.16 3891.48,11324.16 3892.8,11322.85 3892.8,11295.91 3890.8,11293.91 3859.35,11293.91 3849.01,11304.25
  pour cut-out: 2207.37,2010.23 ccw(c2214.2,2010.23) 2209.37,2005.4 ccw(c2216.62,2012.64) 2216.62,2002.4 2233.72,2002.4 ccw(c2233.72,2016.06) 2243.37,2006.4 ccw(c2236.13,2013.64) 2246.37,2013.64 2246.37,2027.74 ccw(c2232.72,2027.74) 2242.37,2037.4 ccw(c2237.54,2032.57) 2237.54,2039.4 2220.44,2039.4 ccw(c2220.44,2022.33) 2208.37,2034.4 ccw(c2210.79,2031.99) 2207.37,2031.99
  pour cut-out: 2207.37,1978.73 ccw(c2214.2,1978.73) 2209.37,1973.9 ccw(c2216.62,1981.15) 2216.62,1970.9 2233.72,1970.9 ccw(c2233.72,1984.56) 2243.37,1974.9 ccw(c2236.13,1982.15) 2246.37,1982.15 2246.37,1996.25 ccw(c2232.72,1996.25) 2242.37,2005.9 ccw(c2237.54,2001.08) 2237.54,2007.9 2220.44,2007.9 ccw(c2220.44,1990.83) 2208.37,2002.9 ccw(c2210.79,2000.49) 2207.37,2000.49
  pour cut-out: 2207.37,1884.24 ccw(c2214.2,1884.24) 2209.37,1879.42 ccw(c2216.62,1886.66) 2216.62,1876.42 2233.72,1876.42 ccw(c2233.72,1890.07) 2243.37,1880.42 ccw(c2236.13,1887.66) 2246.37,1887.66 2246.37,1901.76 ccw(c2232.72,1901.76) 2242.37,1911.42 ccw(c2237.54,1906.59) 2237.54,1913.42 2220.44,1913.42 ccw(c2220.44,1896.35) 2208.37,1908.42 ccw(c2210.79,1906) 2207.37,1906
  pour cut-out: 2207.37,1852.75 ccw(c2214.2,1852.75) 2209.37,1847.92 ccw(c2216.62,1855.16) 2216.62,1844.92 2233.72,1844.92 ccw(c2233.72,1858.58) 2243.37,1848.92 ccw(c2236.13,1856.16) 2246.37,1856.16 2246.37,1870.26 ccw(c2232.72,1870.26) 2242.37,1879.92 ccw(c2237.54,1875.09) 2237.54,1881.92 2220.44,1881.92 ccw(c2220.44,1864.85) 2208.37,1876.92 ccw(c2210.79,1874.51) 2207.37,1874.51
  pour cut-out: 2207.37,1758.26 ccw(c2214.2,1758.26) 2209.37,1753.43 ccw(c2216.62,1760.67) 2216.62,1750.43 2233.72,1750.43 ccw(c2233.72,1764.09) 2243.37,1754.43 ccw(c2236.13,1761.67) 2246.37,1761.67 2246.37,1775.77 ccw(c2232.72,1775.77) 2242.37,1785.43 ccw(c2237.54,1780.6) 2237.54,1787.43 2220.44,1787.43 ccw(c2220.44,1770.36) 2208.37,1782.43 ccw(c2210.79,1780.02) 2207.37,1780.02
  pour cut-out: 2207.37,1726.76 ccw(c2214.2,1726.76) 2209.37,1721.94 ccw(c2216.62,1729.18) 2216.62,1718.94 2233.72,1718.94 ccw(c2233.72,1732.59) 2243.37,1722.94 ccw(c2236.13,1730.18) 2246.37,1730.18 2246.37,1744.28 ccw(c2232.72,1744.28) 2242.37,1753.94 ccw(c2237.54,1749.11) 2237.54,1755.94 2220.44,1755.94 ccw(c2220.44,1738.86) 2208.37,1750.94 ccw(c2210.79,1748.52) 2207.37,1748.52
  pour cut-out: 2238.87,1758.26 ccw(c2245.7,1758.26) 2240.87,1753.43 ccw(c2248.11,1760.67) 2248.11,1750.43 2265.21,1750.43 ccw(c2265.21,1764.09) 2274.87,1754.43 ccw(c2267.63,1761.67) 2277.87,1761.67 2277.87,1775.77 ccw(c2264.21,1775.77) 2273.87,1785.43 ccw(c2269.04,1780.6) 2269.04,1787.43 2251.94,1787.43 ccw(c2251.94,1770.36) 2239.87,1782.43 ccw(c2242.28,1780.02) 2238.87,1780.02
  pour cut-out: 2270.37,1758.26 ccw(c2277.19,1758.26) 2272.37,1753.43 ccw(c2279.61,1760.67) 2279.61,1750.43 2296.71,1750.43 ccw(c2296.71,1764.09) 2306.37,1754.43 ccw(c2299.12,1761.67) 2309.37,1761.67 2309.37,1775.77 ccw(c2295.71,1775.77) 2305.37,1785.43 ccw(c2300.54,1780.6) 2300.54,1787.43 2283.44,1787.43 ccw(c2283.44,1770.36) 2271.37,1782.43 ccw(c2273.78,1780.02) 2270.37,1780.02
  pour cut-out: 2301.86,1695.27 ccw(c2308.69,1695.27) 2303.86,1690.44 ccw(c2311.1,1697.68) 2311.1,1687.44 2328.2,1687.44 ccw(c2328.2,1701.1) 2337.86,1691.44 ccw(c2330.62,1698.68) 2340.86,1698.68 2340.86,1712.78 ccw(c2327.2,1712.78) 2336.86,1722.44 ccw(c2332.03,1717.61) 2332.03,1724.44 2314.93,1724.44 ccw(c2314.93,1707.37) 2302.86,1719.44 ccw(c2305.28,1717.03) 2301.86,1717.03
  pour cut-out: 2333.36,1695.27 ccw(c2340.19,1695.27) 2335.36,1690.44 ccw(c2342.6,1697.68) 2342.6,1687.44 2359.7,1687.44 ccw(c2359.7,1701.1) 2369.36,1691.44 ccw(c2362.11,1698.68) 2372.36,1698.68 2372.36,1712.78 ccw(c2358.7,1712.78) 2368.36,1722.44 ccw(c2363.53,1717.61) 2363.53,1724.44 2346.43,1724.44 ccw(c2346.43,1707.37) 2334.36,1719.44 ccw(c2336.77,1717.03) 2333.36,1717.03
  pour cut-out: 2427.85,1695.27 ccw(c2434.67,1695.27) 2429.85,1690.44 ccw(c2437.09,1697.68) 2437.09,1687.44 2454.19,1687.44 ccw(c2454.19,1701.1) 2463.85,1691.44 ccw(c2456.6,1698.68) 2466.85,1698.68 2466.85,1712.78 ccw(c2453.19,1712.78) 2462.85,1722.44 ccw(c2458.02,1717.61) 2458.02,1724.44 2440.92,1724.44 ccw(c2440.92,1707.37) 2428.85,1719.44 ccw(c2431.26,1717.03) 2427.85,1717.03
  pour cut-out: 2427.85,1726.76 ccw(c2434.68,1726.76) 2429.85,1721.94 ccw(c2437.09,1729.18) 2437.09,1718.94 2454.19,1718.94 ccw(c2454.19,1732.59) 2463.85,1722.94 ccw(c2456.61,1730.18) 2466.85,1730.18 2466.85,1744.28 ccw(c2453.19,1744.28) 2462.85,1753.94 ccw(c2458.02,1749.11) 2458.02,1755.94 2440.92,1755.94 ccw(c2440.92,1738.86) 2428.85,1750.94 ccw(c2431.27,1748.52) 2427.85,1748.52
  pour cut-out: 2459.34,1726.76 ccw(c2466.17,1726.76) 2461.34,1721.94 ccw(c2468.58,1729.18) 2468.58,1718.94 2485.68,1718.94 ccw(c2485.68,1732.59) 2495.34,1722.94 ccw(c2488.1,1730.18) 2498.34,1730.18 2498.34,1744.28 ccw(c2484.68,1744.28) 2494.34,1753.94 ccw(c2489.51,1749.11) 2489.51,1755.94 2472.41,1755.94 ccw(c2472.41,1738.86) 2460.34,1750.94 ccw(c2462.76,1748.52) 2459.34,1748.52
  pour cut-out: 2459.34,1695.27 ccw(c2466.17,1695.27) 2461.34,1690.44 ccw(c2468.58,1697.68) 2468.58,1687.44 2485.68,1687.44 ccw(c2485.68,1701.1) 2495.34,1691.44 ccw(c2488.1,1698.68) 2498.34,1698.68 2498.34,1712.78 ccw(c2484.68,1712.78) 2494.34,1722.44 ccw(c2489.51,1717.61) 2489.51,1724.44 2472.41,1724.44 ccw(c2472.41,1707.37) 2460.34,1719.44 ccw(c2462.76,1717.03) 2459.34,1717.03
  pour cut-out: 2490.84,1726.76 ccw(c2497.67,1726.76) 2492.84,1721.94 ccw(c2500.08,1729.18) 2500.08,1718.94 2517.18,1718.94 ccw(c2517.18,1732.59) 2526.84,1722.94 ccw(c2519.6,1730.18) 2529.84,1730.18 2529.84,1744.28 ccw(c2516.18,1744.28) 2525.84,1753.94 ccw(c2521.01,1749.11) 2521.01,1755.94 2503.91,1755.94 ccw(c2503.91,1738.86) 2491.84,1750.94 ccw(c2494.25,1748.52) 2490.84,1748.52
  pour cut-out: 2490.84,1695.27 ccw(c2497.67,1695.27) 2492.84,1690.44 ccw(c2500.08,1697.68) 2500.08,1687.44 2517.18,1687.44 ccw(c2517.18,1701.1) 2526.84,1691.44 ccw(c2519.6,1698.68) 2529.84,1698.68 2529.84,1712.78 ccw(c2516.18,1712.78) 2525.84,1722.44 ccw(c2521.01,1717.61) 2521.01,1724.44 2503.91,1724.44 ccw(c2503.91,1707.37) 2491.84,1719.44 ccw(c2494.25,1717.03) 2490.84,1717.03
  pour cut-out: 2522.33,1726.76 ccw(c2529.16,1726.76) 2524.33,1721.94 ccw(c2531.58,1729.18) 2531.58,1718.94 2548.68,1718.94 ccw(c2548.68,1732.59) 2558.33,1722.94 ccw(c2551.09,1730.18) 2561.33,1730.18 2561.33,1744.28 ccw(c2547.68,1744.28) 2557.33,1753.94 ccw(c2552.51,1749.11) 2552.51,1755.94 2535.4,1755.94 ccw(c2535.4,1738.86) 2523.33,1750.94 ccw(c2525.75,1748.52) 2522.33,1748.52
  pour cut-out: 2522.33,1695.27 ccw(c2529.16,1695.27) 2524.33,1690.44 ccw(c2531.58,1697.68) 2531.58,1687.44 2548.68,1687.44 ccw(c2548.68,1701.1) 2558.33,1691.44 ccw(c2551.09,1698.68) 2561.33,1698.68 2561.33,1712.78 ccw(c2547.68,1712.78) 2557.33,1722.44 ccw(c2552.51,1717.61) 2552.51,1724.44 2535.4,1724.44 ccw(c2535.4,1707.37) 2523.33,1719.44 ccw(c2525.75,1717.03) 2522.33,1717.03
  pour cut-out: 2522.33,1758.26 ccw(c2529.16,1758.26) 2524.33,1753.43 ccw(c2531.58,1760.67) 2531.58,1750.43 2548.68,1750.43 ccw(c2548.68,1764.09) 2558.33,1754.43 ccw(c2551.09,1761.67) 2561.33,1761.67 2561.33,1775.77 ccw(c2547.68,1775.77) 2557.33,1785.43 ccw(c2552.51,1780.6) 2552.51,1787.43 2535.4,1787.43 ccw(c2535.4,1770.36) 2523.33,1782.43 ccw(c2525.75,1780.02) 2522.33,1780.02
  pour cut-out: 2553.83,1758.26 ccw(c2560.66,1758.26) 2555.83,1753.43 ccw(c2563.07,1760.67) 2563.07,1750.43 2580.17,1750.43 ccw(c2580.17,1764.09) 2589.83,1754.43 ccw(c2582.59,1761.67) 2592.83,1761.67 2592.83,1775.77 ccw(c2579.17,1775.77) 2588.83,1785.43 ccw(c2584,1780.6) 2584,1787.43 2566.9,1787.43 ccw(c2566.9,1770.36) 2554.83,1782.43 ccw(c2557.24,1780.02) 2553.83,1780.02
  pour cut-out: 2522.33,1978.73 ccw(c2529.16,1978.73) 2524.33,1973.9 ccw(c2531.58,1981.15) 2531.58,1970.9 2548.68,1970.9 ccw(c2548.68,1984.56) 2558.33,1974.9 ccw(c2551.09,1982.15) 2561.33,1982.15 2561.33,1996.25 ccw(c2547.68,1996.25) 2557.33,2005.9 ccw(c2552.51,2001.08) 2552.51,2007.9 2535.4,2007.9 ccw(c2535.4,1990.83) 2523.33,2002.9 ccw(c2525.75,2000.49) 2522.33,2000.49
  pour cut-out: 2553.83,1978.73 ccw(c2560.66,1978.73) 2555.83,1973.9 ccw(c2563.07,1981.15) 2563.07,1970.9 2580.17,1970.9 ccw(c2580.17,1984.56) 2589.83,1974.9 ccw(c2582.59,1982.15) 2592.83,1982.15 2592.83,1996.25 ccw(c2579.17,1996.25) 2588.83,2005.9 ccw(c2584,2001.08) 2584,2007.9 2566.9,2007.9 ccw(c2566.9,1990.83) 2554.83,2002.9 ccw(c2557.24,2000.49) 2553.83,2000.49
  pour cut-out: 2553.83,1947.24 ccw(c2560.66,1947.24) 2555.83,1942.41 ccw(c2563.07,1949.65) 2563.07,1939.41 2580.17,1939.41 ccw(c2580.17,1953.07) 2589.83,1943.41 ccw(c2582.59,1950.65) 2592.83,1950.65 2592.83,1964.75 ccw(c2579.17,1964.75) 2588.83,1974.41 ccw(c2584,1969.58) 2584,1976.41 2566.9,1976.41 ccw(c2566.9,1959.34) 2554.83,1971.41 ccw(c2557.24,1968.99) 2553.83,1968.99
  pour cut-out: 2524.08,1948.98 ccw(c2530.91,1948.98) 2526.08,1944.15 ccw(c2533.33,1951.4) 2533.33,1941.15 2550.43,1941.15 ccw(c2550.43,1954.81) 2560.08,1945.15 ccw(c2552.84,1952.4) 2563.08,1952.4 2563.08,1966.5 ccw(c2549.43,1966.5) 2559.08,1976.15 ccw(c2554.26,1971.33) 2554.26,1978.15 2537.15,1978.15 ccw(c2537.15,1961.08) 2525.08,1973.15 ccw(c2527.5,1970.74) 2524.08,1970.74
  pour cut-out: 2522.33,1915.74 ccw(c2529.16,1915.74) 2524.33,1910.91 ccw(c2531.58,1918.15) 2531.58,1907.91 2548.68,1907.91 ccw(c2548.68,1921.57) 2558.33,1911.91 ccw(c2551.09,1919.15) 2561.33,1919.15 2561.33,1933.26 ccw(c2547.68,1933.26) 2557.33,1942.91 ccw(c2552.51,1938.08) 2552.51,1944.91 2535.4,1944.91 ccw(c2535.4,1927.84) 2523.33,1939.91 ccw(c2525.75,1937.5) 2522.33,1937.5
  pour cut-out: 2553.83,1915.74 ccw(c2560.66,1915.74) 2555.83,1910.91 ccw(c2563.07,1918.15) 2563.07,1907.91 2580.17,1907.91 ccw(c2580.17,1921.57) 2589.83,1911.91 ccw(c2582.59,1919.15) 2592.83,1919.15 2592.83,1933.26 ccw(c2579.17,1933.26) 2588.83,1942.91 ccw(c2584,1938.08) 2584,1944.91 2566.9,1944.91 ccw(c2566.9,1927.84) 2554.83,1939.91 ccw(c2557.24,1937.5) 2553.83,1937.5
  pour cut-out: 2522.33,1884.24 ccw(c2529.16,1884.24) 2524.33,1879.41 ccw(c2531.58,1886.65) 2531.58,1876.41 2548.68,1876.41 ccw(c2548.68,1890.07) 2558.33,1880.41 ccw(c2551.09,1887.65) 2561.33,1887.65 2561.33,1901.76 ccw(c2547.68,1901.76) 2557.33,1911.41 ccw(c2552.51,1906.58) 2552.51,1913.41 2535.4,1913.41 ccw(c2535.4,1896.34) 2523.33,1908.41 ccw(c2525.75,1906) 2522.33,1906
  pour cut-out: 2553.83,1884.24 ccw(c2560.66,1884.24) 2555.83,1879.42 ccw(c2563.07,1886.66) 2563.07,1876.42 2580.17,1876.42 ccw(c2580.17,1890.07) 2589.83,1880.42 ccw(c2582.59,1887.66) 2592.83,1887.66 2592.83,1901.76 ccw(c2579.17,1901.76) 2588.83,1911.42 ccw(c2584,1906.59) 2584,1913.42 2566.9,1913.42 ccw(c2566.9,1896.34) 2554.83,1908.42 ccw(c2557.24,1906) 2553.83,1906
  pour cut-out: 2522.33,1852.75 ccw(c2529.16,1852.75) 2524.33,1847.92 ccw(c2531.58,1855.16) 2531.58,1844.92 2548.68,1844.92 ccw(c2548.68,1858.58) 2558.33,1848.92 ccw(c2551.09,1856.16) 2561.33,1856.16 2561.33,1870.26 ccw(c2547.68,1870.26) 2557.33,1879.92 ccw(c2552.51,1875.09) 2552.51,1881.92 2535.4,1881.92 ccw(c2535.4,1864.85) 2523.33,1876.92 ccw(c2525.75,1874.51) 2522.33,1874.51
  pour cut-out: 2555.99,1850.59 ccw(c2562.82,1850.59) 2557.99,1845.76 ccw(c2565.23,1853.01) 2565.23,1842.76 2582.33,1842.76 ccw(c2582.33,1856.42) 2591.99,1846.76 ccw(c2584.74,1854.01) 2594.99,1854.01 2594.99,1868.11 ccw(c2581.33,1868.11) 2590.99,1877.76 ccw(c2586.16,1872.93) 2586.16,1879.76 2569.06,1879.76 ccw(c2569.06,1862.69) 2556.99,1874.76 ccw(c2559.4,1872.35) 2555.99,1872.35
  pour cut-out: 2524.08,1823 ccw(c2530.91,1823) 2526.08,1818.17 ccw(c2533.33,1825.41) 2533.33,1815.17 2550.43,1815.17 ccw(c2550.43,1828.83) 2560.08,1819.17 ccw(c2552.84,1826.41) 2563.08,1826.41 2563.08,1840.51 ccw(c2549.43,1840.51) 2559.08,1850.17 ccw(c2554.26,1845.34) 2554.26,1852.17 2537.15,1852.17 ccw(c2537.15,1835.1) 2525.08,1847.17 ccw(c2527.5,1844.76) 2524.08,1844.76
  pour cut-out: 2553.83,1821.25 ccw(c2560.66,1821.25) 2555.83,1816.42 ccw(c2563.07,1823.67) 2563.07,1813.42 2580.17,1813.42 ccw(c2580.17,1827.08) 2589.83,1817.42 ccw(c2582.59,1824.67) 2592.83,1824.67 2592.83,1838.77 ccw(c2579.17,1838.77) 2588.83,1848.42 ccw(c2584,1843.6) 2584,1850.42 2566.9,1850.42 ccw(c2566.9,1833.35) 2554.83,1845.42 ccw(c2557.24,1843.01) 2553.83,1843.01
  pour cut-out: 2524.08,1788.01 ccw(c2530.91,1788.01) 2526.08,1783.18 ccw(c2533.33,1790.42) 2533.33,1780.18 2550.43,1780.18 ccw(c2550.43,1793.84) 2560.08,1784.18 ccw(c2552.84,1791.42) 2563.08,1791.42 2563.08,1805.52 ccw(c2549.43,1805.52) 2559.08,1815.18 ccw(c2554.26,1810.35) 2554.26,1817.18 2537.15,1817.18 ccw(c2537.15,1800.11) 2525.08,1812.18 ccw(c2527.5,1809.76) 2524.08,1809.76
  pour cut-out: 2553.83,1789.76 ccw(c2560.66,1789.76) 2555.83,1784.93 ccw(c2563.07,1792.17) 2563.07,1781.93 2580.17,1781.93 ccw(c2580.17,1795.59) 2589.83,1785.93 ccw(c2582.59,1793.17) 2592.83,1793.17 2592.83,1807.27 ccw(c2579.17,1807.27) 2588.83,1816.93 ccw(c2584,1812.1) 2584,1818.93 2566.9,1818.93 ccw(c2566.9,1801.86) 2554.83,1813.93 ccw(c2557.24,1811.51) 2553.83,1811.51
  pour cut-out: 2427.85,2041.72 ccw(c2434.67,2041.72) 2429.85,2036.9 ccw(c2437.09,2044.14) 2437.09,2033.9 2454.19,2033.9 ccw(c2454.19,2047.55) 2463.85,2037.9 ccw(c2456.6,2045.14) 2466.85,2045.14 2466.85,2059.24 ccw(c2453.19,2059.24) 2462.85,2068.9 ccw(c2458.02,2064.07) 2458.02,2070.9 2440.92,2070.9 ccw(c2440.92,2053.83) 2428.85,2065.9 ccw(c2431.26,2063.48) 2427.85,2063.48
  pour cut-out: 2429.11,2011.49 ccw(c2435.93,2011.49) 2431.11,2006.66 ccw(c2438.35,2013.9) 2438.35,2003.66 2455.45,2003.66 ccw(c2455.45,2017.32) 2465.11,2007.66 ccw(c2457.86,2014.9) 2468.11,2014.9 2468.11,2029 ccw(c2454.45,2029) 2464.11,2038.66 ccw(c2459.28,2033.83) 2459.28,2040.66 2442.18,2040.66 ccw(c2442.18,2023.59) 2430.11,2035.66 ccw(c2432.52,2033.25) 2429.11,2033.25
  pour cut-out: 2459.34,2041.72 ccw(c2466.17,2041.72) 2461.34,2036.9 ccw(c2468.58,2044.14) 2468.58,2033.9 2485.68,2033.9 ccw(c2485.68,2047.55) 2495.34,2037.9 ccw(c2488.1,2045.14) 2498.34,2045.14 2498.34,2059.24 ccw(c2484.68,2059.24) 2494.34,2068.9 ccw(c2489.51,2064.07) 2489.51,2070.9 2472.41,2070.9 ccw(c2472.41,2053.83) 2460.34,2065.9 ccw(c2462.76,2063.48) 2459.34,2063.48
  pour cut-out: 2459.34,2010.23 ccw(c2466.17,2010.23) 2461.34,2005.4 ccw(c2468.58,2012.64) 2468.58,2002.4 2485.68,2002.4 ccw(c2485.68,2016.06) 2495.34,2006.4 ccw(c2488.1,2013.64) 2498.34,2013.64 2498.34,2027.74 ccw(c2484.68,2027.74) 2494.34,2037.4 ccw(c2489.51,2032.57) 2489.51,2039.4 2472.41,2039.4 ccw(c2472.41,2022.33) 2460.34,2034.4 ccw(c2462.76,2031.99) 2459.34,2031.99
  pour cut-out: 2490.84,2041.72 ccw(c2497.67,2041.72) 2492.84,2036.9 ccw(c2500.08,2044.14) 2500.08,2033.9 2517.18,2033.9 ccw(c2517.18,2047.55) 2526.84,2037.9 ccw(c2519.6,2045.14) 2529.84,2045.14 2529.84,2059.24 ccw(c2516.18,2059.24) 2525.84,2068.9 ccw(c2521.01,2064.07) 2521.01,2070.9 2503.91,2070.9 ccw(c2503.91,2053.83) 2491.84,2065.9 ccw(c2494.25,2063.48) 2490.84,2063.48
  pour cut-out: 2490.84,2010.23 ccw(c2497.67,2010.23) 2492.84,2005.4 ccw(c2500.08,2012.64) 2500.08,2002.4 2517.18,2002.4 ccw(c2517.18,2016.06) 2526.84,2006.4 ccw(c2519.6,2013.64) 2529.84,2013.64 2529.84,2027.74 ccw(c2516.18,2027.74) 2525.84,2037.4 ccw(c2521.01,2032.57) 2521.01,2039.4 2503.91,2039.4 ccw(c2503.91,2022.33) 2491.84,2034.4 ccw(c2494.25,2031.99) 2490.84,2031.99
  pour cut-out: 2522.33,2010.23 ccw(c2529.16,2010.23) 2524.33,2005.4 ccw(c2531.58,2012.64) 2531.58,2002.4 2548.68,2002.4 ccw(c2548.68,2016.06) 2558.33,2006.4 ccw(c2551.09,2013.64) 2561.33,2013.64 2561.33,2027.74 ccw(c2547.68,2027.74) 2557.33,2037.4 ccw(c2552.51,2032.57) 2552.51,2039.4 2535.4,2039.4 ccw(c2535.4,2022.33) 2523.33,2034.4 ccw(c2525.75,2031.99) 2522.33,2031.99
  pour cut-out: 2522.33,2041.72 ccw(c2529.16,2041.72) 2524.33,2036.9 ccw(c2531.58,2044.14) 2531.58,2033.9 2548.68,2033.9 ccw(c2548.68,2047.55) 2558.33,2037.9 ccw(c2551.09,2045.14) 2561.33,2045.14 2561.33,2059.24 ccw(c2547.68,2059.24) 2557.33,2068.9 ccw(c2552.51,2064.07) 2552.51,2070.9 2535.4,2070.9 ccw(c2535.4,2053.83) 2523.33,2065.9 ccw(c2525.75,2063.48) 2522.33,2063.48
  pour cut-out: 2333.36,2041.72 ccw(c2340.19,2041.72) 2335.36,2036.9 ccw(c2342.6,2044.14) 2342.6,2033.9 2359.7,2033.9 ccw(c2359.7,2047.55) 2369.36,2037.9 ccw(c2362.11,2045.14) 2372.36,2045.14 2372.36,2059.24 ccw(c2358.7,2059.24) 2368.36,2068.9 ccw(c2363.53,2064.07) 2363.53,2070.9 2346.43,2070.9 ccw(c2346.43,2053.83) 2334.36,2065.9 ccw(c2336.77,2063.48) 2333.36,2063.48
  pour cut-out: 2301.86,2041.72 ccw(c2308.69,2041.72) 2303.86,2036.9 ccw(c2311.1,2044.14) 2311.1,2033.9 2328.2,2033.9 ccw(c2328.2,2047.55) 2337.86,2037.9 ccw(c2330.62,2045.14) 2340.86,2045.14 2340.86,2059.24 ccw(c2327.2,2059.24) 2336.86,2068.9 ccw(c2332.03,2064.07) 2332.03,2070.9 2314.93,2070.9 ccw(c2314.93,2053.83) 2302.86,2065.9 ccw(c2305.28,2063.48) 2301.86,2063.48
  text "'.Layer_Name'" at -2296.32,-2314.1 h60
Multi-Layer:
  drawing of 162 lines, arcs and shapes, not listed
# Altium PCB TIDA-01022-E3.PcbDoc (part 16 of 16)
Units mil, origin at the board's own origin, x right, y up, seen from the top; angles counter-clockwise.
Board outline 6929.13 x 11614.17 mil, 12 copper layers (L1_Top Layer, L2_GND, L3_GND, L4_Signal Layer 1, L5_GND, L6_PWR, L7_GND/PWR, L8_PWR, L9_GND/PWR, L10_Signal Layer 2, L11_GND, L12_Bottom Layer), stack 64.6 mil thick; 1733 components, 993 nets, 5987 pads, 3555 vias.

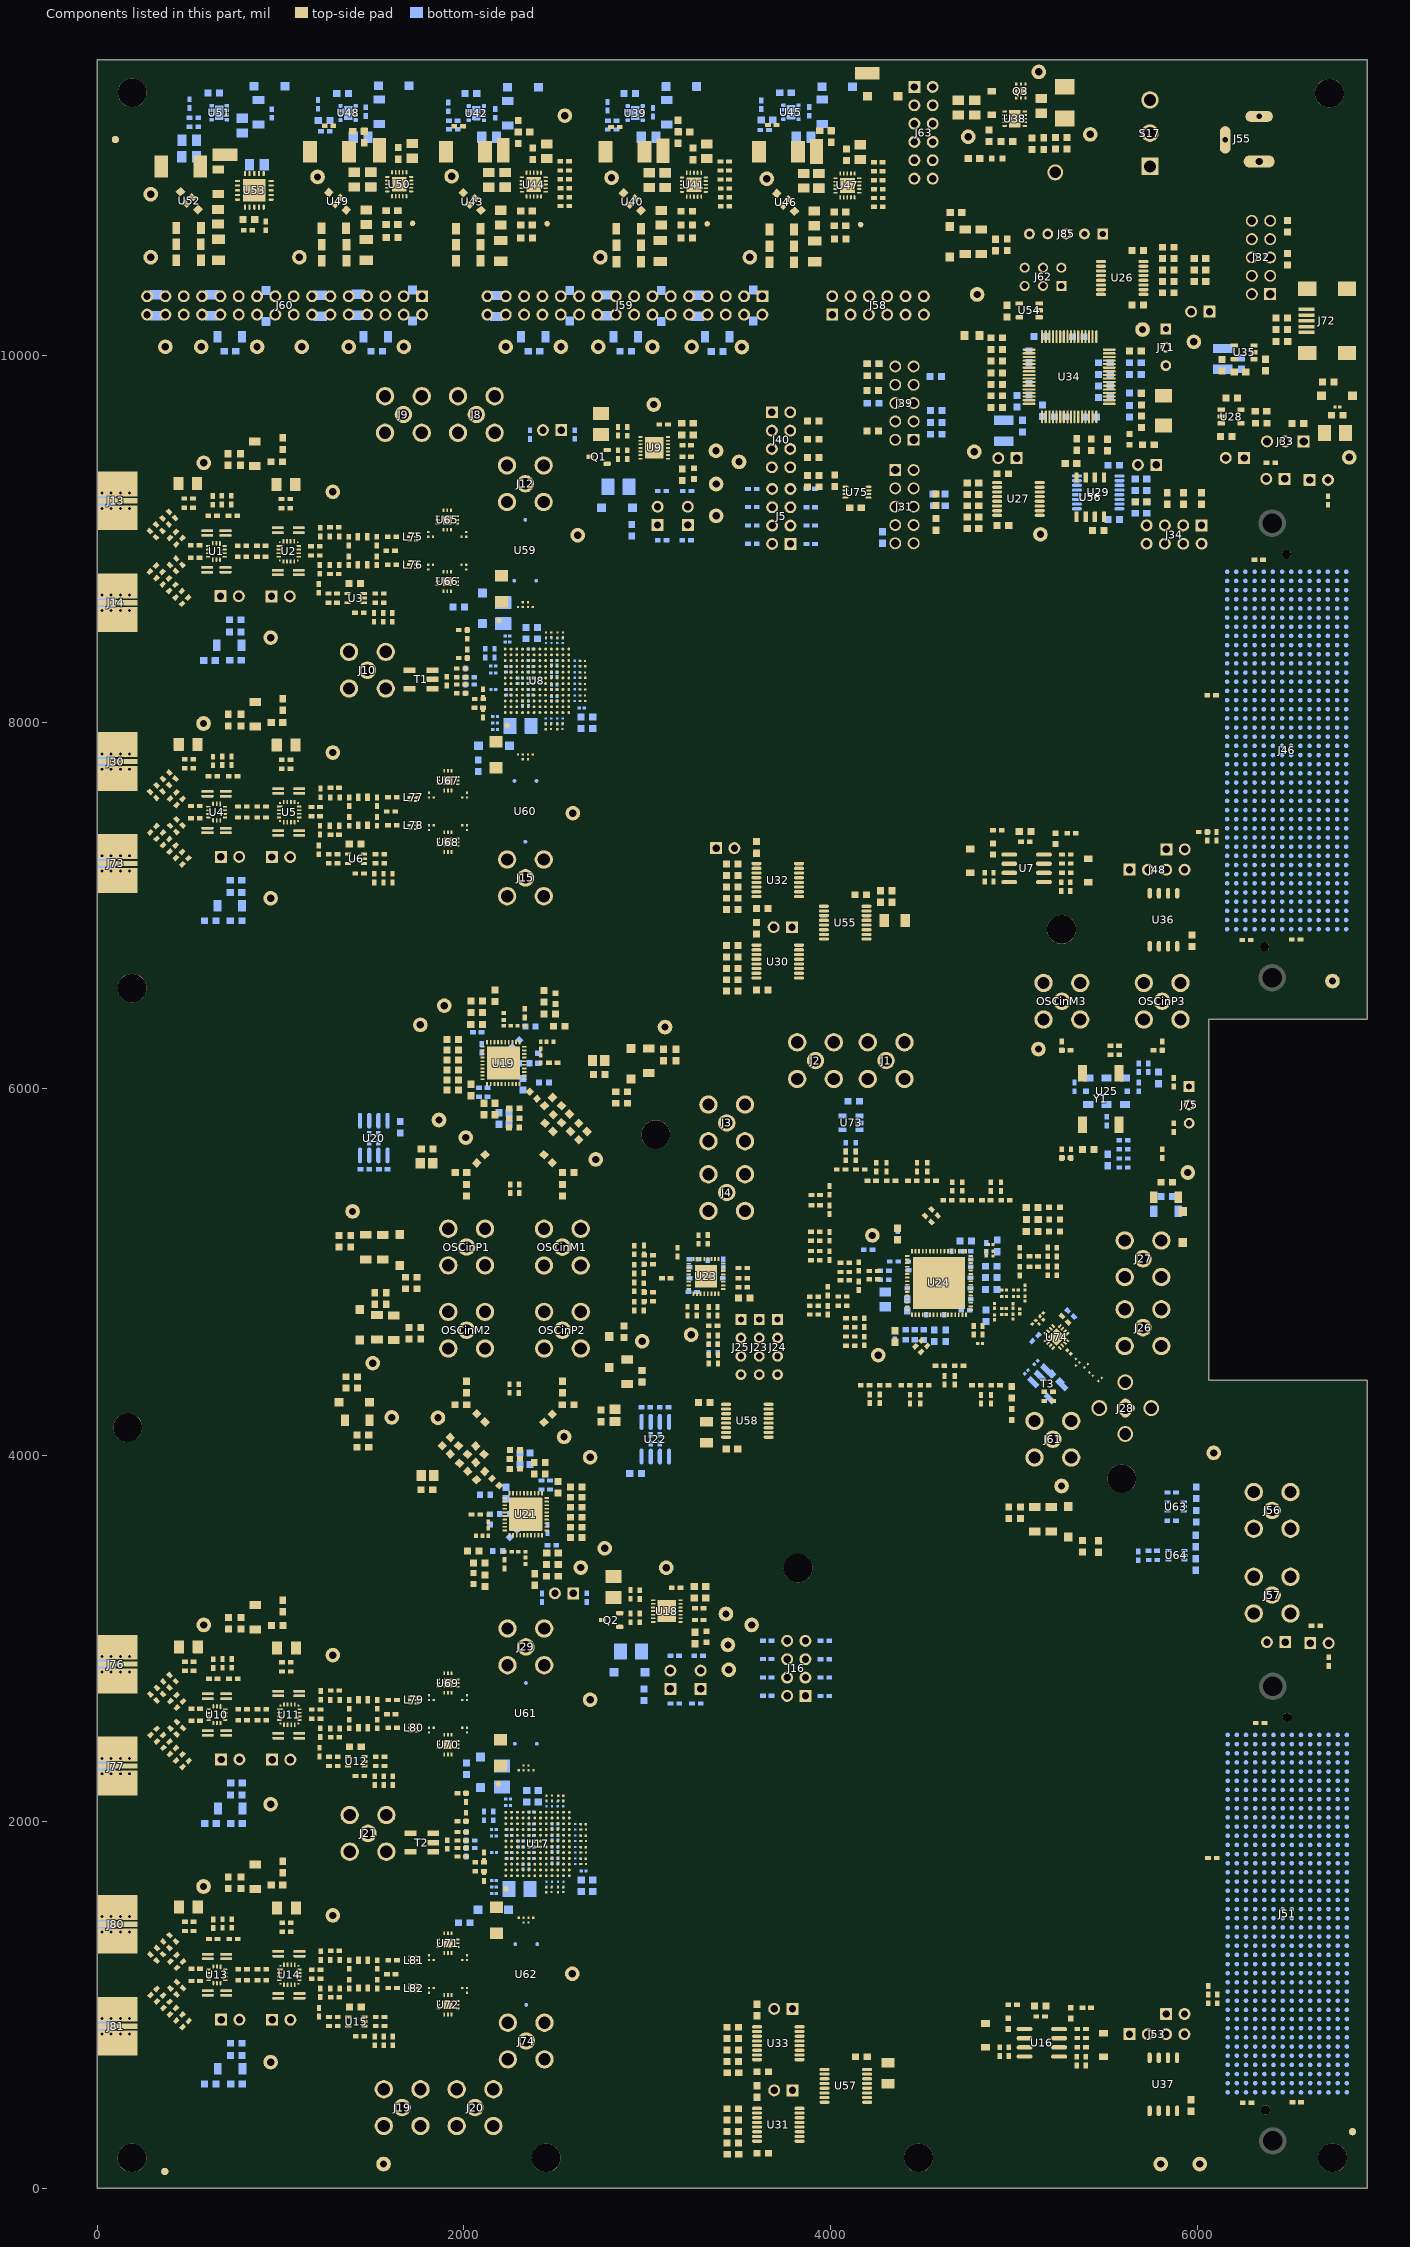
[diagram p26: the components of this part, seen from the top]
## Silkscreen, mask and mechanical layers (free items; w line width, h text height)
Top Overlay:
  drawing of 617 lines, arcs and shapes, not listed
  text "GND1" at 5198.73,11552 h25
  text "12VIN" at 3992.45,11514 h25
  text "12V_DC" at 5378,11275 h25
  text "GND" at 2419.2,11270 h25
  text "12V" at 4622,11174 h25
  text "12V_DCIN" at 6542,11129 h40
  text "ON/OFF" at 5621,11110 h30 r90
  text "EN/UVLO" at 5314,10966 h25
  text "12VIN_LED" at 4792,10948 h30
  text "3P3_CONV" at 3589,10792.51 h25 r90
  text "VA2P5_CONV" at 1091.38,10791.85 h25 r90
  text "V1P1V_CONV" at 1869,10748 h25 r90
  text "V1P9V_CONV" at 2735,10745.89 h25 r90
  text "VA_N2P5_CONV" at 220,10711.85 h25 r90
  text "USB2ANY-1" at 6232,10459 h25 r90
  text "GND" at 3527,10450 h25
  text "GND" at 1075.54,10446 h25
  text "GND" at 264,10441 h25
  text "GND" at 2720.77,10437.82 h25
  text "GND" at 3236,10425 h25
  text "GND" at 446,10422 h25
  text "VA_N2P5_IN" at 745,10422 h25
  text "GND" at 1246,10422 h25
  text "VA2P5_IN" at 1575,10422 h25
  text "GND" at 2190,10422 h25
  text "V1P1V_IN" at 2443,10422 h25
  text "V1P9V_IN" at 2944,10422 h25
  text "V3P3_IN" at 3428.18,10417 h25
  text "GND" at 4593,10289 h25 r90
  text "V3P3_VDD" at 4684,10243 h25
  text "PWR_SYNC" at 3753,10204 h25
  text "DGND" at 4593,10177 h25 r90
  text "USB_ACTIVITY" at 4370,10093 h25
  text "3P3USB" at 5594,10078 h25 r90
  text "DGND" at 5948,9948 h25
  text "DGND" at 2704.77,9926 h25
  text "DGND" at 2196,9925 h25
  text "AGND" at 1332,9923 h25
  text "DGND" at 3212,9923 h25
  text "VA_N2P5" at 783,9922 h25
  text "AGND" at 1072,9922 h25
  text "VA2P5" at 1608,9922 h25
  text "V1P1V" at 2492,9922 h25
  text "AGND" at 529,9921 h25
  text "V1P9V" at 2986,9921 h25
  text "AGND" at 331,9920 h25
  text "V3P3" at 3480,9920 h25
  text "1" at 3608,9693 h25
  text "2" at 3840,9693 h25
  text "TDIODE1-" at 2431,9657 h25 r90
  text "TDIODE1+" at 2544,9653 h25 r90
  text "USB2ANY-2" at 4549,9638 h25 r90
  text "1P8V_USB" at 4697,9582 h25
  text "1" at 4528,9524 h25
  text "ANALOG I/P" at 32,9517 h40
  text "VCC_LMH5401" at 589.04,9513 h30 r90
  text "2" at 4273,9513 h25
  text "TMSTP1+" at 1993,9471 h30
  text "TMSTP1-" at 1588,9469 h30
  text "CH1" at 106.68,9447.9 h40
  text "1" at 4271,9358 h25
  text "2" at 4514,9358 h25
  text "ANALOG I/P" at 1738.47,9354 h40
  text "AGND" at 1238.81,9324 h25
  text "VREGIN" at 5590,9308 h25 r90
  text "CH1_AC_COUP" at 1733,9290 h40
  text "C" at 1555.81,9240.81 h20
  text "VDDL19" at 6845,9233.78 h25 r90
  text "VD1P1_ADC1" at 2545,9094 h25
  text "USB2ANY-3" at 4292,9059 h25 r90
  text "PD1" at 2923,9055 h25
  text "CALTRG1" at 3288,9026 h25
  text "DGND" at 5213,8995 h25
  text "2" at 3599,8957 h25
  text "1" at 3842,8956 h25
  text "C" at 1271.14,8927.02 h20
  text "VA1P1_ADC1" at 1930,8561.9 h25
  text "A" at 2677.79,8374.81 h20
  text "VEE_LMH5401" at 787,8338 h30
  text "T1" at 1750,8323 h25
  text "VCC_LMH5401" at 586.54,8097.69 h30 r90
  text "ANALOG I/P" at 41.68,8079.64 h40
  text "DEVCLKIN1" at 1388,8039 h30
  text "CH2" at 109,8019 h40
  text "AGND" at 1251.81,7902.37 h25
  text "D" at 1611.79,7826.87 h20
  text "VA1P9_ADC1" at 2256,7694 h25 r90
  text "FMC+_1 CONNECTOR" at 6842.11,7675.67 h60 r90
  text "A" at 3005,7549.67 h20
  text "D" at 1272.94,7504.89 h20
  text "DGND" at 2666,7476 h25
  text "FMC_SDA1" at 5635,7256 h25 r90
  text "FMC_SCL1" at 5736,7255 h25 r90
  text "3P3VAUX1" at 5993,7181 h25
  text "DGND" at 5795,7107 h25
  text "VEE_LMH5401" at 790.23,6906 h30
  text "ANALOG I/P" at 2194.68,6900.9 h40
  text "CH2_AC_COUP" at 2195,6837 h40
  text "LMK_OSCIN_P/N" at 5303.86,6697 h40
  text "V3P3_LMX1RF" at 2968,6407 h30
  text "INPUT COUPLING TYPE SELECTION" at 351.82,6358 h25
  text "ANALOG" at 89,6296 h25
  text "INPUT" at 327.5,6293.32 h25
  text "RESISTOT JUMPER SETTING" at 683.33,6266 h25
  text "COUPLING" at 325,6252 h25
  text "INPUT" at 91,6251 h25
  text "DGND" at 4975,6185 h25
  text "TRANSFORMER" at 301,6128 h25
  text "R551,R552-Populate / R592,R604-Not populate" at 685,6085 h25
  text "CH1" at 117,6076 h25
  text "LMH5401+LMH6401" at 274,6018 h25
  text "R551,R552-Not populate / R592, R604-Populate" at 682,5970 h25
  text "SDCLKOUT13_P/N" at 3923,5930 h30
  text "EN" at 5835.06,5900.52 h25
  text "TRANSFORMER" at 301,5900 h25
  text "R560,R561-Populate / R605,R606-Not populate" at 685,5857 h25
  text "CH2" at 117,5848 h25
  text "LMH5401+LMH6401" at 274,5790 h25
  text "R560,R561-Not populate / R605,R606-Populate" at 682,5742 h25
  text "TRANSFORMER" at 301,5672 h25
  text "DGND" at 1926,5641 h25
  text "R569,R570-Populate / R607,R608-Not populate" at 685,5629 h25
  text "CH3" at 117,5620 h25
  text "LMH5401+LMH6401" at 274,5562 h25
  text "V3P3_LMK61E2" at 5538,5543 h30
  text "R569,R570-Not populate / R607,R608-Populate" at 685,5510 h25
  text "TRANSFORMER" at 301,5444 h25
  text "V3P3_LMX1" at 1350,5439.29 h30
  text "DCLKOUT12_P/N" at 3643,5430 h30 r90
  text "R578,R579-Populate / R609,R610-Not populate" at 685,5401 h25
  text "CH4" at 117,5392 h25
  text "LMH5401+LMH6401" at 274,5334 h25
  text "R578,R579-Not populate / R609,R610-Populate" at 684,5288 h25
  text "J62 CONNECTOR" at 367.82,5017 h25
  text "PIN NO" at 89.82,4960 h25
  text "OPERATION/FUNCTION" at 466,4960 h25
  text "PIN NO" at 257.82,4958 h25
  text "2" at 330.82,4905 h25
  text "1" at 141.82,4901 h25
  text "SHORT/DEFAULT" at 510,4880 h25
  text "3" at 139.82,4839 h25
  text "4" at 331.82,4837 h25
  text "OPEN/USB2ANY" at 512,4797 h25
  text "5" at 137.82,4783 h25
  text "6" at 329.82,4775 h25
  text "CLKIN0_P/N" at 5944,4641 h40 r90
  text "DGND" at 3176,4609 h25 r90
  text "V3P3_LMX2" at 1176,4487 h30
  text "DGND" at 4328,4482 h25
  text "V3P3_LMK00304" at 3088,4333 h30 r90
  text "DGND" at 2612,4084 h25
  text "DGND" at 6041,4077 h25
  text "V3P3_LMX2RF" at 1707.43,4067.1 h30 r90
  text "RESET" at 4930,4006 h25
  text "LMK_CLKIN" at 5681.08,3996 h40 r45
  text "SYNCSE_EXTIN" at 6258,3885 h25
  text "V3P3_LMK48xx" at 4832.23,3793.01 h30
  text "TIDA-01022-E3" at 70.09,3778.39 h100
  text "SYNCSE_EXTOUT" at 6258,3413 h25
  text "VCC_LMH5401" at 590.04,3176.32 h30 r90
  text "ANALOG I/P" at 44.76,3157.86 h40
  text "CH3" at 112,3099 h40
  text "ANALOG I/P" at 1722.54,3071.42 h40
  text "CH3_AC_COUP" at 1717.54,3012.42 h40
  text "AGND" at 1250.41,2984.64 h25
  text "TDIODE2+" at 2619,2968 h25 r90
  text "TDIODE2-" at 2579,2967 h25 r90
  text "E" at 1591.52,2945.67 h20
  text "VD1P1_ADC2" at 2590,2741.98 h25
  text "PD2" at 2969,2700 h25
  text "CALTRG2" at 3369,2667 h25
  text "2" at 3681,2643 h25
  text "1" at 3926,2641 h25
  text "E" at 1281.98,2581.75 h20
  text "VA1P1_ADC2" at 1907,2216 h25
  text "B" at 2672,2036.77 h20
  text "VEE_LMH5401" at 801,1998 h30
  text "VCC_LMH5401" at 573.87,1750 h30 r90
  text "ANALOG I/P" at 42.92,1749.27 h40
  text "DEVCLKIN2" at 1400,1695 h30
  text "CH4" at 110,1688 h40
  text "AGND" at 1238.68,1559.57 h25
  text "F" at 1618.98,1509.69 h20
  text "VA1P9_ADC2" at 2260,1323 h25 r90
  text "B" at 3023.33,1197.07 h20
  text "FMC+_2 CONNECTOR" at 6826.44,1174.79 h60 r90
  text "F" at 1283.98,1155.75 h20
  text "DGND" at 2661,1138 h25
  text "FMC_SDA2" at 5634.19,902.71 h25 r90
  text "FMC_SCL2" at 5735.19,901.71 h25 r90
  text "3P3VAUX2" at 5992.19,827.71 h25
  text "ANALOG I/P" at 2555.68,763.9 h40
  text "DGND" at 5794.19,753.71 h25
  text "CH4_AC_COUP" at 2554,704 h40
  text "TMSTP2-" at 1943.68,626.9 h30
  text "TMSTP2+" at 1544.68,623.9 h30
  text "VEE_LMH5401" at 794,586 h30
  text "DGND" at 1631,83 h25
  text "DGND" at 5759.3,40 h25
  text "TOP OVERLAY" at -2293.76,-2323.68 h50
Bottom Overlay:
  drawing of 151 lines, arcs and shapes, not listed
  text "-2.5V" at 408,11552 h25
  text "GND" at 1817.57,11552 h25
  text "GND" at 2689.57,11551 h25
  text "GND" at 3530.57,11549 h25
  text "GND" at 1119,11548 h25
  text "GND" at 147.57,10585 h25
  text "A" at 2619,8420.12 h25
  text "A" at 1599,7563 h25
  text "B" at 2646.59,2069.34 h25
  text "B" at 1567.64,1363.13 h25
  text "BOTTOM OVERLAY" at -2179.53,-2337.19 h50
Top Paste:
  text "TOP PASTE" at -2293.76,-2323.68 h60
Bottom Paste:
  text "BOTTOM PASTE" at -2293.76,-2323.68 h60
Top Solder:
  lines w9: 1705.5,9011.13 1705.63,9011 ; 1708.89,1245.44 1709.02,1245.3 ; 1737.13,9011 1745,9011 ; 1740.44,2664.64 1748.32,2664.64 ; 1804.69,9011 1805.01,9010.68
  lines w9.84: 1697.76,9011 1705.63,9011 ; 1701.15,1245.3 1709.02,1245.3
  lines w11: 321.8,7431.87 356.8,7396.87 ; 1526.69,2557.28 1526.69,2566.83 ; 1526.69,2603.4 1526.69,2566.83 ; 1526.69,2617.44 1526.69,2606.26 1534.32,2598.64 ; 1542.45,2587.64 1545.32,2587.64 ; 1579.69,2587.64 1545.32,2587.64 ; 1583.71,9011.05 1583.76,9011 ; 1748.32,2512.64 1748.62,2512.34 ; 1748.39,1093.3 1748.69,1093 ; 1808.33,1094.22 1808.63,1093.92 ; 1808.33,2513.32 1808.63,2513.02 ; 1526.69,2566.83 1534.65,2574.79 ; 1534.32,2598.64 1534.32,2575.13 1534.65,2574.79 ; 1534.32,2598.64 1545.32,2587.64 ; 1534.65,2574.79 1546.41,2586.55 1545.32,2587.64
  text "TOP SOLDER" at -2293.76,-2323.68 h60
Bottom Solder:
  text "BOTTOM SOLDER" at -2293.76,-2323.68 h60
Drill Guide:
  text ".Layer_Name" at -2293.76,-2323.68 h60
M1 Board Outline:
  the board outline again, w10
  text "Build on TIDA-01022 PCB" at -1712,-1662 h72.83
M2 Board Dimensions:
  rectangle: -2871.26,-1750.69 -2746.26,-1625.69
  rectangle: -2746.26,-1875.69 -2371.26,-1750.69
  lines w7: -2871.26,-1750.69 -1871.26,-1750.69 ; -2746.26,-1875.69 -2746.26,-1625.69 ; -2621.26,-1875.69 -2621.26,-1625.69 ; -2371.26,-1875.69 -2371.26,-1625.69 ; -2121.26,-1875.69 -2121.26,-1625.69 ; -2871.26,-1875.69 -1871.26,-1875.69 -1871.26,-1625.69 -2871.26,-1625.69 -2871.26,-1875.69
  lines w10: -2871.26,-1940.69 -2871.26,-1920.69 ; -2811.26,-1950.69 -2871.26,-1930.69 ; -2811.26,-1910.69 -2871.26,-1930.69 ; -2647.17,-1930.69 -2871.26,-1930.69 ; -2095.34,-1930.69 -1871.26,-1930.69 ; -1931.26,-1950.69 -1871.26,-1930.69 ; -1931.26,-1910.69 -1871.26,-1930.69 ; -1871.26,-1940.69 -1871.26,-1920.69
  text "1000 (mil)" at -2637.17,-1966.68 h60
M3 3D STEP Top:
  text ".Layer_Name" at -2293.76,-2323.68 h60
M4 3D STEP Bottom:
  text ".Layer_Name" at -2293.76,-2323.68 h60
M5 Assembly Top:
  circle w6: c6112,9705.47 r7.62
  circle w10: c6603,10119 r11.26
  circle w10: c6397,10332.42 r15.13
  circle w6: c1470,885 r5.1
  circle w6: c1471,7228.54 r6.62
  circle w6: c1473,2304.31 r8.31
  circle w6: c1471,8650.67 r6.74
  circle w6: c4355,9375 r24.52
  circle w6: c4453,9540 r16.49
  circle w6: c5155,10210 r6.08
  circle w6: c5258,10379 r17.72
  circle w6: c5825,10146 r15.52
  circle w6: c6311,9952.47 r7.62
  circle w6: c6577,9532 r8
  circle w6: c5490,10661 r19.42
  circle w6: c5739,10995 r26
  circle w6: c3723,10871 r12.65
  circle w6: c2884,10874 r12.65
  circle w6: c2011,10874 r12.65
  circle w6: c1276.65,10875.19 r12.65
  circle w6: c468,10875 r12.65
  circle w6: c3513,4741 r12.65
  circle w6: c3611,4743 r12.65
  circle w6: c3713,4741 r12.65
  circle w6: c5956,6011.36 r12.72
  lines w6: 2893,4863 2780,4863 2780,5069 2896,5069 ; 2895,4968 2871,4968 ; 4954,4698 4954,4732 ; 5036,4843 5036,4826.28 5047.75,4814.53 5061,4801.28 5061,4698 5093,4666 5093,4438 4863,4438 4863,4937 5037,4937 5037,4925 ; 5235,4834 5206,4805 ; 6928.6,10336.23 6928.6,10041.37 6559.63,10041.37 6559.63,10340.37 6932.74,10340.37 ; 2871,4968 2871,4967 2879,4959 2879,4976 2871,4968 ; 4954,4732 4955,4732 4962,4725 4947,4725 4954,4732 ; 5206,4805 5219,4805 5206,4818 5206,4805 ; 300.46,10962.1 300.46,11099.9 607.54,11099.9 607.54,10962.1 300.46,10962.1 ; 1113.46,11043.43 1113.46,11181.22 1420.54,11181.22 1420.54,11043.43 1113.46,11043.43 ; 1855.03,11043.34 1855.03,11181.14 2162.12,11181.14 2162.12,11043.34 1855.03,11043.34 ; 2724.75,11043.1 2724.75,11180.9 3031.84,11180.9 3031.84,11043.1 2724.75,11043.1 ; 3561.46,11043.1 3868.54,11043.1 3868.54,11180.9 3561.46,11180.9 3561.46,11043.1 ; 5071,4701 5071,4743 5087,4759 5379,5051 5450,4980 5478,4952 5353,4827 5281,4827 5192,4738 5113,4659 5071,4701
  lines w10: -3162.76,-2395.36 3437.24,-2395.36 ; -3162.76,-2192.02 3439.24,-2192.02 ; -3162.76,-1988.69 -3162.76,-2598.69 842.24,-2598.69 3439.24,-2598.69 3439.24,-1988.69 -3162.26,-1988.69 -3162.26,-2598.69 -1586.76,-2598.69 ; -697.76,-2598.69 -697.76,-1988.69 ; 569.24,-2192.02 569.24,-1988.69 ; 1409.24,-2192.02 1409.24,-1988.69 ; 2031.24,-2605.19 2031.24,-2402.36
  text "L68" at 1237,11107 h20
  text "L58" at 1980.57,11103.24 h20
  text "L57" at 2850.29,11103 h20
  text "L59" at 3687,11103 h20
  text "L69" at 426,11022 h20
  text "J72" at 6689,10177 h20
  text "A" at 4798,10056 h20
  text "K" at 4738,10055 h20
  text "U74" at 5214,4625 h20 r45
  text "COMPONENTS MARKED 'DNP' SHOULD NOT BE POPULATED." at -1717.26,-1783.69 h20
  text "ASSEMBLY VARIANT:" at -1717.76,-1899.19 h20
  text ".VariantName" at -681.76,-1899.19 h20
  text "E3" at 1004.47,-2114.19 h20
  text "PCB VIEWED FROM TOP SIDE" at -3099.26,-2120.86 h20
  text "BOARD #:" at -622.76,-2120.86 h20
  text "TIDA-010128" at -77.26,-2120.86 h20
  text "REV:" at 767.24,-2120.86 h20
  text "SVN REV:" at 1605.24,-2120.86 h20
  text "ASSEMBLY TOP" at -2287.53,-2318.19 h20
  text "TID #:" at -623.76,-2318.86 h20
  text "010128" at -284.32,-2320.1 h20
  text "LAYER NAME =" at -3099.26,-2323.68 h20
  text "PLOT NAME =" at -3099.26,-2529.53 h20
  text ".plot_File_Name" at -2293.76,-2529.53 h20
  text "GENERATED    :" at -620.76,-2529.53 h20
  text "03/05/2017" at 248.74,-2529.53 h20
  text "12:12:36 PM" at 977.74,-2529.53 h20
  text "TEXAS INSTRUMENTS" at 2242.24,-2529.53 h20
M6 Assembly Bottom:
  circle w6: c4165,5848 r6.71
  circle w6: c5944,3479.41 r4.52
  circle w6: c5942,3745.69 r5.78
  lines w6: 2280,8184 2280,8139 2321,8139 ; 2286,8274 2286,8364 2640,8364 2730,8454 3043,8454 3043,8099.87 2646.42,8099.87 ; 2288,1936 2288,2022 2689,2022 2755,2088 3152,2088 3152,1806 3152,1675 2831,1675 2752.13,1753.87 2649.75,1753.87 ; 2290,1831 2290,1793 2325,1793 ; 2386,1775 2398,1763 2448,1763 ; 2393.44,8130.61 2425.72,8098.32 2461.16,8098.32 ; 2524.15,8098.32 2585.82,8098.32 ; 2538,1759 2581,1759 ; 2662,8258 2705,8258 ; 2688,1880 2759,1880 ; 2705,8258 2705,8256 2699,8250 2699,8264 2705,8258 ; 2759,1880 2751,1872 2751,1888 2759,1880 ; 4025,5746 4199,5746 4199,5861 4187,5873 4025,5873 4025,5746
  lines w10: -3163.26,-2192.52 3438.74,-2192.52 ; -3161.26,-2395.86 3438.74,-2395.86 ; -1755.26,-2605.69 -1755.26,-2402.86 ; -1133.26,-2192.52 -1133.26,-1989.19 ; -293.26,-2192.52 -293.26,-1989.19 ; 973.74,-2599.19 973.74,-1989.19 ; 1862.74,-2599.19 3438.24,-2599.19 3438.24,-1989.19 -3163.26,-1989.19 -3163.26,-2599.19 -566.26,-2599.19 3438.74,-2599.19 3438.74,-1989.19
  text "T3" at 5185,4366 h20 r315
  text "COMPONENTS MARKED 'DNP' SHOULD NOT BE POPULATED." at 3231.24,-1783.19 h20
  text ".VariantName" at 2187.24,-1899.19 h20
  text "ASSEMBLY VARIANT:" at 3226.24,-1899.19 h20
  text "SVN REV:" at -1329.26,-2121.36 h20
  text "REV:" at -491.26,-2121.36 h20
  text "TIDA-010128" at 353.24,-2121.36 h20
  text "BOARD #:" at 898.74,-2121.36 h20
  text "PCB VIEWED FROM BOTTOM SIDE" at 3375.24,-2121.36 h20
  text "E3" at -629.53,-2134.19 h20
  text "ASSEMBLY BOTTOM" at 1901.68,-2314.1 h20
  text "LAYER NAME =" at 3193.61,-2316.68 h20
  text "TID #:" at 921.11,-2325.86 h20
  text "010128" at 581.68,-2327.1 h20
  text "TEXAS INSTRUMENTS" at -1966.26,-2530.03 h20
  text "12:12:36 PM" at -701.76,-2530.03 h20
  text "03/05/2017" at 27.24,-2530.03 h20
  text "GENERATED    :" at 896.74,-2530.03 h20
  text ".plot_File_Name" at 2569.74,-2530.03 h20
  text "PLOT NAME =" at 3375.24,-2530.03 h20
M9 Title Sheet:
  drawing of 64 lines, arcs and shapes, not listed
  text "1" at -1987.2,15167.81 h70
  text "2" at 508.46,15167.81 h70
  text "3" at 2997.81,15167.81 h70
  text "4" at 5504.48,15167.81 h70
  text "5" at 8003.46,15167.81 h70
  text "6" at 10508.46,15167.81 h70
  text "A" at 16491.46,5429.81 h70
  text "A" at -3287.26,5428.31 h70
  text "B" at 16491.46,3049.81 h70
  text "B" at -3287.26,3048.31 h70
  text "C" at 16491.46,674.81 h70
  text "C" at -3287.26,673.31 h70
  text ".PRJ_Title" at 13501.46,-1319.52 h70
  text "DESIGNED FOR:" at 13451.46,-1487.19 h45
  text ".PRJ_Customer" at 13501.46,-1627.19 h70
  text "D" at 16491.46,-1695.19 h70
  text "D" at -3287.26,-1696.69 h70
  text "FILE NAME:" at 13451.46,-1787.19 h45
  text ".PCB_File_Name_No_Path" at 13501.46,-1907.19 h70
  text "Texas Instruments (TI) and/or its licensors do not warrant the accuracy or completeness of this specification" at 3503.24,-2070.53 h45
  text "ENGINEER:" at 13451.46,-2077.19 h45
  text "LAYOUT BY:" at 14956.46,-2077.19 h45
  text "or any information contained therein. TI and/or its licensors do not warrant that this design will meet" at 3458.26,-2183.2 h45
  text ".PRJ_Engineer" at 13501.46,-2232.18 h70
  text ".PCB_Layout" at 15006.96,-2232.18 h70
  text "the specifications, will be suitable for your application or fit for any particular purpose, or will operate in" at 3458.26,-2295.86 h45
  text "ALTIUM DESIGNER VERSION:" at 14956.46,-2387.19 h45
  text "an implementation. TI and/or its licensors do not warrant that the design is production worthy. You should" at 3458.26,-2408.53 h45
  text ".print_Scale" at 13501.46,-2520.52 h70
  text ".Application_BuildNumber" at 15006.96,-2520.52 h70
  text "completely validate and test your design implementation to confirm the system functionality for your application." at 3503.24,-2521.19 h45
  text "6" at 15343.46,-2727.19 h70
  text "1" at -2130.92,-2728.69 h70
  text "2" at 364.74,-2728.69 h70
  text "3" at 2854.09,-2728.69 h70
  text "4" at 5360.76,-2728.69 h70
  text "5" at 7859.74,-2728.69 h70
M10 Fab Notes:
  drawing of 244 lines, arcs and shapes, not listed
  text "DESIGN INFORMATION" at 14488.98,5346.31 h60
  text "(REFER ALSO ARRAY/PANEL PROFILING INFORMATION)" at 14127.42,5184.59 h60
  text "BOARD SIZE" at 13441.42,5180.31 h60
  text "296MM" at 14589.18,5056.31 h60
  text "X" at 14409.42,5052.49 h60
  text "176MM" at 13844.18,5046.31 h60
  text "Number of Layers :" at 13844.42,4855.31 h60
  text "12" at 14939.24,4845.31 h60
  text "MIN. TRACK WIDTH:" at 13844.42,4716.31 h60
  text "MIL" at 15095.42,4716.31 h60
  text "3.5" at 14880,4715 h60
  text "5" at 14875.18,4586.31 h60
  text "MIN. CLEARANCE:" at 13844.42,4584.31 h60
  text "MIL" at 15095.42,4584.31 h60
  text "16" at 14894.68,4459.9 h60
  text "MIN. VIA PAD SIZE:" at 13844.42,4452.31 h60
  text "MIL" at 15095.42,4452.31 h60
  text "4 MIL" at 14539.42,4310.6 h60
  text "MINIMUM ANNULAR RING" at 13515.19,4306.31 h60
  text "EXTERNAL" at 15352.18,4306.31 h60
  text "PER" at 13715.19,4188.31 h60
  text "IPC-D-275 CLASS 2 LEVEL C" at 13935.19,4188.31 h60
  text "+/-" at 15030.96,4075.31 h60
  text "MIL, HOLES" at 15423.42,4076.02 h60
  text "+/-" at 15884.96,4075.31 h60
  text "5" at 15291.17,4070.31 h60
  text "3" at 16124.17,4070.31 h60
  text "REGISTRATION TOLERANCES:" at 13515.19,4070.31 h60
  text "METAL" at 14714.96,4070.31 h60
  text "MIL" at 16240.42,4070.31 h60
  text "MATERIAL:" at 13440.42,3860.85 h60
  text "R-5670K AND R-5775K" at 15679.68,3722.9 h40
  text "FR-4 High Tg" at 14426.87,3720.52 h60
  text "X" at 15151.68,3718.9 h60
  text "FR-408" at 13861.43,3711.95 h60
  text "OTHER" at 15349.42,3711.95 h60
  text "63 MIL (1.6mm) +/-10%" at 14181.53,3549.23 h60
  text "THICKNESS:" at 13515.19,3544.95 h60
  text "X" at 14053.36,3544.95 h60
  text "OTHER" at 15466.42,3544.95 h60
  text "TOLERANCE:" at 13515.19,3386.95 h60
  text "X" at 14354.5,3386.95 h60
  text "ANSI IPC-6012 TYPE 3 CLASS 2" at 14541.44,3386.95 h60
  text "OTHER +/-" at 14541.42,3230.95 h60
  text "BOW & TWIST:" at 13515.19,3073.95 h60
  text "X" at 14354.5,3073.95 h60
  text "ANSI IPC-6012 TYPE 3 CLASS 2" at 14541.44,3073.95 h60
  text "OTHER +/-" at 14541.42,2915.44 h60
  text "COPPER THICKNESS (FINISHED):" at 13440.42,2779.95 h60
  text "1.4MIL (1oz)" at 14320.42,2627.23 h60
  text "2MIL (1.4oz)" at 15087.42,2627.23 h60
  text "2.8MIL (2oz)" at 15814.42,2627.23 h60
  text "OUTER:" at 13797.42,2622.95 h60
  text "X" at 14191.96,2622.31 h60
  text "N/A" at 15813.96,2470.59 h60
  text "0.6MIL (1/2oz)" at 14320.42,2470.23 h60
  text "2.8MIL (2oz)" at 15087.42,2470.23 h60
  text "INNER SIGNAL:" at 13508.34,2465.95 h60
  text "X" at 14191.96,2462.31 h60
  text "DRILLING:" at 13440.42,2326.95 h60
  text "REFERENCE:" at 13515.19,2209.95 h60
  text "X" at 14163.42,2209.95 h60
  text "AS SHOWN" at 14350.42,2209.95 h60
  text "X" at 15064.42,2209.95 h60
  text "NC_DRILL FILES" at 15201.42,2209.95 h60
  text "PTH MIN COPPER THICKNESS:" at 13515.19,2051.95 h60
  text "X" at 14865.42,2051.95 h60
  text "1MIL" at 15002.42,2051.95 h60
  text "OTHER" at 15499.42,2051.95 h60
  text "BOARD FINISH:" at 13440.42,1892.95 h60
  text "SILKSCREEN:" at 13595.65,1774.95 h60
  text "X" at 14544.42,1774.95 h60
  text "TOP" at 14670.42,1774.95 h60
  text "X" at 15054.42,1774.95 h60
  text "BOTTOM" at 15181.42,1774.95 h60
  text "SILKSCREEN COLOR:" at 13595.65,1607.95 h60
  text "X" at 14543.38,1607.95 h60
  text "WHITE" at 14670.42,1607.95 h60
  text "OTHER" at 15181.42,1607.95 h60
  text "SOLDER RESIST COLOR:" at 13595.65,1437.95 h60
  text "X" at 14163.39,1278.75 h60
  text "GREEN" at 14290.42,1278.75 h60
  text "BLUE" at 14881.42,1278.75 h60
  text "OTHER" at 15419.42,1278.75 h60
  text "IMMERSION GOLD (ENIG)" at 14501.42,1090.23 h60
  text "ENEPIG" at 15838.96,1086.95 h60
  text "SURFACE FINISH:" at 13440.42,1085.95 h60
  text "X" at 14314.48,1085.95 h60
  text "IMPEDANCE TABLE:-" at 7683.42,1066.9 h60
  text "IMM. TIN/SILVER OR EQUIV" at 13769.96,928.95 h60
  text "OTHER" at 15201.42,928.95 h60
  text "ARRAY/PANEL:" at 13440.42,749.95 h60
  text "CUT AND TRIM PER MECH LAYER 1" at 14501.42,745.66 h60
  text "N.C. ROUTE" at 14501.42,593.95 h60
  text "X" at 15180.42,593.95 h60
  text "V. SCORE" at 15367.42,593.95 h60
  text "100 OHM DIFF" at 10810.68,588.9 h50
  text "Layer" at 7781.68,587.9 h50
  text "100 OHM DIFF" at 9956.68,583.9 h50
  text "50 OHM SE" at 8380.68,543.9 h50
  text "90 OHM DIFF" at 8972.68,540.9 h50
  text "REFERENCE" at 11595.42,521.9 h50
  text "LOOSELY COUPLED" at 10751.68,512.9 h50
  text "TIGHTLY COUPLED" at 9897.68,507.9 h50
  text "CERTIFICATION:" at 13440.42,456.95 h60
  text "MATERIALS AND WORKMANSHIP FOR ALL PCBS" at 14165.42,456.95 h60
  text "Layer" at 11678.42,414.9 h50
  text "WIDTH/SPACING" at 8978.68,391.9 h50
  text "WIDTH/SPACING" at 10816.68,387.9 h50
  text "TRACE WIDTH" at 8237.68,383.9 h50
  text "WIDTH/SPACING" at 9962.68,382.9 h50
  text "TO MEET OR EXCEED THE REQUIREMENTS OF:" at 14165.42,358.95 h60
  text "(MILS)" at 9112.68,285.9 h50
  text "(MILS)" at 10950.68,281.9 h50
  text "(MILS)" at 8349.68,277.9 h50
  text "(MILS)" at 10096.68,276.9 h50
  text "X" at 13791.93,222.44 h60
  text "ANSI IPC-A-600F CLASS ->" at 13930.93,222.44 h60
  text "X" at 15569.98,222.44 h60
  text "2" at 15688.93,222.44 h60
  text "1" at 15373.93,220.95 h60
  text "3" at 16042.93,220.95 h60
  text "+/-10%" at 9103.68,198.9 h50
  text "+/-10%" at 10941.68,194.9 h50
  text "+/-10%" at 8340.68,190.9 h50
  text "+/-10%" at 10087.68,189.9 h50
  text "L2_GND" at 11675.68,75.9 h50
  text "L1_Top" at 7779.83,74.9 h50
  text "8.2mil trace/" at 9091.42,72.9 h50
  text "6mil trace/" at 9982.42,67.9 h50
  text "X" at 13793.98,62.95 h60
  text "UL 94V-0" at 13930.93,62.95 h60
  text "X" at 14605.98,62.95 h60
  text "RoHS" at 14742.93,62.95 h60
  text "OTHER" at 15387.33,62.95 h60
  text "PER ORDER" at 15784.39,62.95 h60
  text "10mil trace/" at 10904.42,60.9 h50
  text "11mils" at 8336.68,23.9 h50
  text "Layer" at 11679.68,-2.1 h50
  text "6mil space" at 9093.42,-10.1 h50
  text "Layer" at 7788.68,-15.1 h50
  text "5mil space" at 9984.42,-15.1 h50
  text "18mil space" at 10906.42,-22.1 h50
  text "ADDITIONAL REQUIREMENTS:" at 13440.42,-78.05 h60
  text "X" at 15424.26,-78.58 h60
  text "VIA TENTING:" at 14657.96,-78.69 h60
  text "YES" at 15207.63,-87.77 h60
  text "NO" at 15572.44,-93 h60
  text "L4_SIGNAL" at 7763.94,-147.1 h50
  text "4.9mil trace/" at 9973.42,-161.1 h50
  text "L5_GND" at 11670.68,-163.1 h50
  text "MICROSECTION:" at 13515.19,-193.05 h60
  text "YES" at 14420.93,-193.05 h60
  text "X" at 15892.68,-195.1 h60
  text "NIL" at 11039.68,-199.1 h50
  text "NIL" at 9199.68,-202.1 h50
  text "IMPEDANCE CONTROL:" at 14683.96,-202.69 h60
  text "YES" at 15667.96,-203.69 h60
  text "5.5mils" at 8328.68,-208.1 h50
  text "NO" at 16043.44,-221 h60
  text "Layer1" at 7817.68,-231.1 h50
  text "Layer" at 11674.68,-241.1 h50
  text "7.1mil space" at 9975.42,-244.1 h50
  text "REQUIRED" at 15282.42,-349.2 h60
  text "BARE BOARD ELEC. TEST:" at 13515.19,-352.05 h60
  text "NONE" at 14820.93,-352.05 h60
  text "X" at 15155.42,-352.05 h60
  text "PER ORDER" at 15874.42,-352.05 h60
  text "L10_SIGNAL" at 7716.94,-373.1 h50
  text "L11_GND" at 11696.68,-377.1 h50
  text "6.3mil trace/" at 10887.42,-379.1 h50
  text "5.5mil trace/" at 9968.42,-381.1 h50
  text "NIL" at 9197.68,-422.1 h50
  text "6.5mils" at 8321.68,-425.1 h50
  text "Layer" at 11700.68,-455.1 h50
  text "Layer2" at 7817.68,-458.1 h50
  text "20.1mil space" at 10889.42,-462.1 h50
  text "6.5mil space" at 9970.42,-464.1 h50
  text "MANUFACTURER'S UL:" at 13515.19,-509.05 h60
  text "RAIL" at 14680.93,-513.34 h60
  text "METAL" at 15172.74,-513.34 h60
  text "SILK" at 15684.42,-513.34 h60
  text "X" at 15547.96,-513.69 h60
  text "L12_BOTTOM" at 7719.83,-597.1 h50
  text "10mil trace/" at 10887.42,-602.1 h50
  text "L11_GND" at 11693.68,-611.1 h50
  text "6mil trace/" at 9966.42,-613.1 h50
  text "11mils" at 8309.68,-646.1 h50
  text "NIL" at 9201.68,-673.1 h50
  text "Layer" at 7816.68,-684.1 h50
  text "18mil space" at 10889.42,-685.1 h50
  text "Layer" at 11697.68,-689.1 h50
  text "5mil space" at 9968.42,-696.1 h50
M11 Gerber Information:
  lines w10: -3162.76,-2395.36 3437.24,-2395.36 ; -3162.76,-2192.02 3439.24,-2192.02 ; -3162.76,-1988.69 -3162.76,-2598.69 842.24,-2598.69 3439.24,-2598.69 3439.24,-1988.69 -3162.26,-1988.69 -3162.26,-2598.69 -1586.76,-2598.69 ; -697.76,-2598.69 -697.76,-1988.69 ; 569.24,-2192.02 569.24,-1988.69 ; 1409.24,-2192.02 1409.24,-1988.69 ; 2031.24,-2605.19 2031.24,-2402.36
  text "E3" at 1060.47,-2116.19 h40
  text "ALL ARTWORK VIEWED FROM TOP SIDE" at -3099.26,-2120.86 h60
  text "BOARD #:" at -622.76,-2120.86 h60
  text "TIDA-010128" at -77.26,-2120.86 h60
  text "REV:" at 767.24,-2120.86 h60
  text "SVN REV:" at 1605.24,-2120.86 h60
  text "TID #:" at -623.76,-2320.86 h60
  text "010128" at -284.32,-2322.1 h60
  text "LAYER NAME =" at -3097.26,-2323.68 h60
  text "PLOT NAME =" at -3099.26,-2529.53 h60
  text ".plot_File_Name" at -2293.76,-2529.53 h60
  text "GENERATED    :" at -620.76,-2529.53 h60
  text "'.Print_Date'" at 248.74,-2529.53 h60
  text "'.Print_Time'" at 977.74,-2529.53 h60
  text "TEXAS INSTRUMENTS" at 2242.24,-2529.53 h60
M12 Stackup:
  drawing of 711 lines, arcs and shapes, not listed
  text "STACKUP:-" at 7625.42,4857.9 h60
  text "Layer" at 7653.5,4547.5 h60
  text "Name" at 8063.41,4547.5 h60
  text "Material" at 9233.08,4547.5 h60
  text "Thickness" at 10092.85,4547.5 h60
  text "Constant" at 10742.68,4547.5 h60
  text "Board Layer Stack" at 11312.54,4547.5 h60
  text "1" at 7653.5,4427.5 h60
  text "Top Overlay" at 8063.41,4427.5 h60
  text "2" at 7653.5,4307.5 h60
  text "Top Solder" at 8063.41,4307.5 h60
  text "Solder Resist" at 9233.08,4307.5 h60
  text "0.40mil" at 10092.85,4307.5 h60
  text "3.5" at 10742.68,4307.5 h60
  text "3" at 7653.5,4187.5 h60
  text "L1_Top Layer" at 8063.41,4187.5 h60
  text "Copper" at 9233.08,4187.5 h60
  text "1.40mil" at 10092.85,4187.5 h60
  text "4" at 7653.5,4067.5 h60
  text "Dielectric1" at 8063.41,4067.5 h60
  text "R-5670k" at 9233.08,4067.5 h60
  text "5.60mil" at 10092.85,4067.5 h60
  text "4.2" at 10742.68,4067.5 h60
  text "5" at 7653.5,3947.5 h60
  text "L2_GND" at 8063.41,3947.5 h60
  text "Copper" at 9233.08,3947.5 h60
  text "0.60mil" at 10092.85,3947.5 h60
  text "6" at 7653.5,3827.5 h60
  text "Dielectric 2" at 8063.41,3827.5 h60
  text "R-5775K" at 9233.08,3827.5 h60
  text "5.00mil" at 10092.85,3827.5 h60
  text "4.2" at 10742.68,3827.5 h60
  text "7" at 7653.5,3707.5 h60
  text "L3_GND" at 8063.41,3707.5 h60
  text "Copper" at 9233.08,3707.5 h60
  text "0.60mil" at 10092.85,3707.5 h60
  text "8" at 7653.5,3587.5 h60
  text "Dielectric 3" at 8063.41,3587.5 h60
  text "R-5670k" at 9233.08,3587.5 h60
  text "7.50mil" at 10092.85,3587.5 h60
  text "4.2" at 10742.68,3587.5 h60
  text "9" at 7653.5,3467.5 h60
  text "L4_Signal Layer 1" at 8063.41,3467.5 h60
  text "Copper" at 9233.08,3467.5 h60
  text "0.60mil" at 10092.85,3467.5 h60
  text "10" at 7653.5,3347.5 h60
  text "Dielectric 4" at 8063.41,3347.5 h60
  text "R-5775K" at 9233.08,3347.5 h60
  text "4.00mil" at 10092.85,3347.5 h60
  text "4.2" at 10742.68,3347.5 h60
  text "11" at 7653.5,3227.5 h60
  text "L5_GND" at 8063.41,3227.5 h60
  text "Copper" at 9233.08,3227.5 h60
  text "0.60mil" at 10092.85,3227.5 h60
  text "12" at 7653.5,3107.5 h60
  text "Dielectric 5" at 8063.41,3107.5 h60
  text "R-5670k" at 9233.08,3107.5 h60
  text "4.30mil" at 10092.85,3107.5 h60
  text "4.2" at 10742.68,3107.5 h60
  text "13" at 7653.5,2987.5 h60
  text "L6_PWR" at 8063.41,2987.5 h60
  text "Copper" at 9233.08,2987.5 h60
  text "0.60mil" at 10092.85,2987.5 h60
  text "14" at 7653.5,2867.5 h60
  text "Dielectric 6" at 8063.41,2867.5 h60
  text "R-5775K" at 9233.08,2867.5 h60
  text "3.00mil" at 10092.85,2867.5 h60
  text "4.2" at 10742.68,2867.5 h60
  text "15" at 7653.5,2747.5 h60
  text "L7_GND/PWR" at 8063.41,2747.5 h60
  text "Copper" at 9233.08,2747.5 h60
  text "0.60mil" at 10092.85,2747.5 h60
  text "16" at 7653.5,2627.5 h60
  text "Dielectric 7" at 8063.41,2627.5 h60
  text "R-5670k" at 9233.08,2627.5 h60
  text "4.30mil" at 10092.85,2627.5 h60
  text "4.2" at 10742.68,2627.5 h60
  text "17" at 7653.5,2507.5 h60
  text "L8_PWR" at 8063.41,2507.5 h60
  text "Copper" at 9233.08,2507.5 h60
  text "0.60mil" at 10092.85,2507.5 h60
  text "18" at 7653.5,2387.5 h60
  text "Dielectric 8" at 8063.41,2387.5 h60
  text "R-5775K" at 9233.08,2387.5 h60
  text "4.00mil" at 10092.85,2387.5 h60
  text "4.2" at 10742.68,2387.5 h60
  text "19" at 7653.5,2267.5 h60
  text "L9_GND/PWR" at 8063.41,2267.5 h60
  text "Copper" at 9233.08,2267.5 h60
  text "0.60mil" at 10092.85,2267.5 h60
  text "20" at 7653.5,2147.5 h60
  text "Dielectric 9" at 8063.41,2147.5 h60
  text "R-5670k" at 9233.08,2147.5 h60
  text "7.50mil" at 10092.85,2147.5 h60
  text "4.2" at 10742.68,2147.5 h60
  text "21" at 7653.5,2027.5 h60
  text "L10_Signal Layer 2" at 8063.41,2027.5 h60
  text "Copper" at 9233.08,2027.5 h60
  text "0.60mil" at 10092.85,2027.5 h60
  text "22" at 7653.5,1907.5 h60
  text "Dielectric 10" at 8063.41,1907.5 h60
  text "R-5775K" at 9233.08,1907.5 h60
  text "5.00mil" at 10092.85,1907.5 h60
  text "4.2" at 10742.68,1907.5 h60
  text "23" at 7653.5,1787.5 h60
  text "L11_GND" at 8063.41,1787.5 h60
  text "Copper" at 9233.08,1787.5 h60
  text "0.60mil" at 10092.85,1787.5 h60
  text "24" at 7653.5,1667.5 h60
  text "Dielectric 11" at 8063.41,1667.5 h60
  text "R-5670k" at 9233.08,1667.5 h60
  text "5.60mil" at 10092.85,1667.5 h60
  text "4.2" at 10742.68,1667.5 h60
  text "25" at 7653.5,1547.5 h60
  text "L12_Bottom Layer" at 8063.41,1547.5 h60
  text "Copper" at 9233.08,1547.5 h60
  text "1.40mil" at 10092.85,1547.5 h60
  text "26" at 7653.5,1427.5 h60
  text "Bottom Solder" at 8063.41,1427.5 h60
  text "Solder Resist" at 9233.08,1427.5 h60
  text "0.40mil" at 10092.85,1427.5 h60
  text "3.5" at 10742.68,1427.5 h60
  text "27" at 7653.5,1307.5 h60
  text "Bottom Overlay" at 8063.41,1307.5 h60
M13 Component Bodies Top:
  text ".Layer_Name" at -2293.76,-2323.68 h60
M14 Component Bodies Bottom:
  text ".Layer_Name" at -2293.76,-2323.68 h60
M15 Courtyards Top:
  text ".Layer_Name" at -2293.76,-2323.68 h60
M16 Courtyards Bottom:
  text ".Layer_Name" at -2293.76,-2323.68 h60
Drill Drawing:
  text ".legend" at 8215.24,7564.81 h60
  text "Drill Table" at 8271.47,7429.81 h60
  text "FOR 8MIL DRILL +0/-8MIL" at 8250.24,7311.81 h60
  text "FOR 10MIL DRILL +0/-10MIL" at 8247.24,7211.81 h60
  text "FOR 12MIL DRILL +0/-12MIL" at 8250.24,7099.81 h60
  text "FOR 16MIL DRILL +0/-16MIL" at 8244.24,7004.81 h60
  text "FOR PTH DRILL +/-3MIL" at 8237.46,6900.81 h60
  text "FOR NPTH DRILL +/-2MIL" at 8237.46,6820.81 h60
  text "NOTE:" at 8213.46,6659.81 h60
  text "1.10 mil Vias are not tented." at 8540,6532 h60
  text "2.Fill all on pad vias and flat the surface ( except 10 mil via)." at 8531,6439 h60
  text "3.Cut the copper 10mil from board edge." at 8534,6329 h60
  text "DRILL DRAWING" at -2293.76,-2323.68 h60
Mechanical 31:
  drawing of 958 lines, arcs and shapes, not listed

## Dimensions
0,11614.17 to 0,0 on M2 Board Dimensions
6929.13,6377.95 to 6929.13,11614.17 on M2 Board Dimensions
6062.99,6377.95 to 6062.99,4409.45 on M2 Board Dimensions
6062.99,4409.45 to 6929.13,4409.45 on M2 Board Dimensions
6929.13,4409.45 to 6929.13,0 on M2 Board Dimensions
0,0 to 6929.13,0 on M2 Board Dimensions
